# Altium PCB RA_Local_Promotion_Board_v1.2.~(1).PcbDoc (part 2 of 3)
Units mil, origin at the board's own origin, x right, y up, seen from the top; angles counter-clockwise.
Board outline 3390.27 x 5338.61 mil, 4 copper layers (Top Layer, Signal Layer 1, Signal Layer 2, Bottom Layer), stack 30.635 mil thick; 143 components, 181 nets, 726 pads, 394 vias.

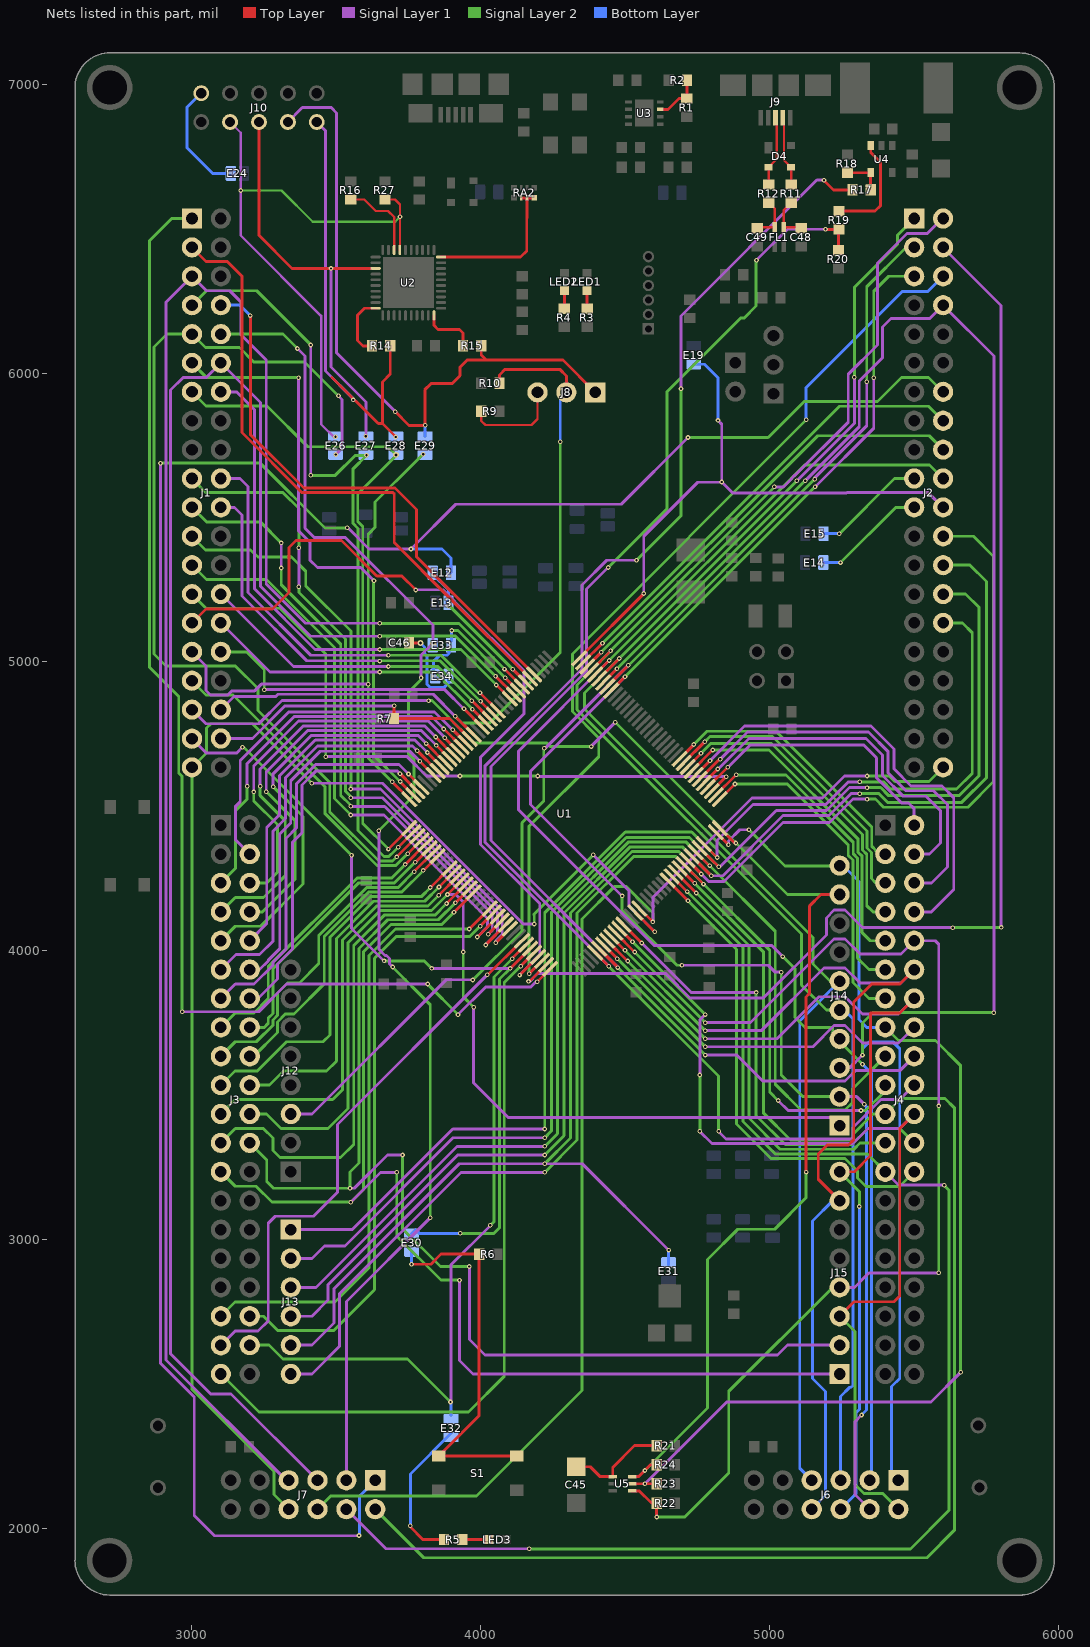
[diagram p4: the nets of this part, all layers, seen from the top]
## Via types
v1: diameter 16, hole 8, Top Layer to Bottom Layer, 368 vias
v2: diameter 19.68, hole 7.87, Top Layer to Bottom Layer, 16 vias
v3: diameter 20, hole 10, Top Layer to Bottom Layer, 7 vias
v4: diameter 16, hole 8, Top Layer to Bottom Layer, tented both sides, 3 vias

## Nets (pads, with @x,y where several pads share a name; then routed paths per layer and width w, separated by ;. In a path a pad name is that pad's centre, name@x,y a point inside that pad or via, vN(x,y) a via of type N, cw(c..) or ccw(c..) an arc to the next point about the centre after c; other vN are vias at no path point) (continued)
NetC45_1: C45.1 R21.2 U5.1 | length 355.9
  Top Layer w10: C45.1@4330,2213.99 4379.01,2213.99 4413.39,2179.61 U5.1@4456.54,2179.61 4456.54,2211.54 4532,2287 R21.2@4608.5,2287
NetC46_1: C46.1 E34.1 | length 325.7
  Top Layer w10: C46.1@3757.5,5066 3790,5066 v3(3791,5066) v3@3794.97,5066
  Bottom Layer w10: v3@3790.02,5065.98 3804.79,5051.21 3804.79,5029.93 3813.65,5021.07 3813.65,4922.93 3824.29,4912.29 3873.53,4912.29 E34.1@3887,4925.76 ; v3@3790.03,5066 v3(3791,5066) ; E34.1@3887,4925.76 3887,4950.36 E34.1@3887.64,4951 3887.64,4926.39 E34.1@3887,4925.76
NetC48_2: C48.2 FL1.2 R11.1 | length 156.8
  Top Layer w8: R11.1@5074,6589.5 5048.87,6564.38 FL1.2@5048.87,6504.54 5105.96,6504.54 C48.2@5109,6501.5
NetC49_2: C49.2 FL1.3 R12.1 | length 155.1
  Top Layer w8: C49.2@4956.61,6501.5 4959.65,6504.54 FL1.3@5017.13,6504.54 5017.13,6569.38 R12.1@4997,6589.5
NetD4_2: D4.2 J9.3 R12.2 | length 246.5
  Top Layer w8: R12.2@4997,6652.5 4997,6711.23 D4.2@4995.63,6712.6 5024,6740.97 J9.3@5024,6886.69
NetD4_3: D4.3 J9.2 R11.2 | length 244.3
  Top Layer w8: J9.2@5049.59,6886.69 5049.59,6736.64 5074,6712.23 R11.2@5074,6652.5
NetE24_2: E24.2 J10.9 | length 397.5
  Bottom Layer w10: J10.9@3032,6969 2983,6920 2983,6780 3072,6691 E24.2@3134.36,6691
NetE26_2: E26.2 J10.8 R27.2 U2.17 | length 2061.7
  Top Layer w8: R27.2@3668,6600.5 3703,6600.5 3720,6583.5 v1(3720,6541) 3720,6426.72 U2.17@3719.47,6426.19
  Signal Layer 1 w8: J10.8@3132,6869 3169,6832 3169,6476 3447,6198 3447,5823 v1@3493.5,5776.5
  Signal Layer 2 w8: v1(3168.87,6632.13) 3309.87,6632.13 3417.87,6524.13 3703.13,6524.13 v1(3720,6541)
  other v1: 3497,5780
NetE27_2: E27.2 J10.6 U2.23 | length 1474.6
  Top Layer w10: J10.6@3232,6869 3232,6477 3346.73,6362.27 v1(3481.27,6362.27) U2.23@3635.81,6362.27
  Signal Layer 1 w10: v1(3481.27,6362.27) 3481.27,6020.73 3602,5900 v1(3602,5781)
NetE28_2: E28.2 J10.2 R14.1 | length 1600.6
  Top Layer w10: 3485,5985 3645,5825 3659.46,5825 ; R14.1@3686.5,6094 3686.5,5996.5 3659.46,5969.46 3659.46,5825 ; v1(3705.76,5778.7) 3659.46,5825
  Signal Layer 1 w10: J10.2@3432,6869 3462,6839 3462,6007 3558,5911 v1(3558,5907)
NetE29_2: E29.2 J8.1 J10.4 R15.1 | length 2353.2
  Top Layer w10: v1(3704,5866) 3751,5819 v1@3806,5819 ; v1(3807,5819) v1@3806,5819 ; R15.1@4001.5,6095 4001.5,6062.5 4019,6045 ; J8.1@4396,5933 4284,6045 4019,6045 ; v1@3806,5819 3806,5942 3828,5964 3901,5964 3928,5991 3928,6020 3953,6045 4019,6045
  Signal Layer 1 w10: J10.4@3332,6869 3382,6919 3482,6919 3500.27,6900.73 3500.27,6354.4 3500,6354.13 3500,6070 v1(3704,5866)
  Bottom Layer w10: E29.2@3807,5780.5 v1(3807,5819)
NetE30_2: E30.2 R6.1 S1.1 S1.4 | length 1317.9
  Top Layer w10: v1(3760,2915) 3827,2915 3862,2950 3993.5,2950 3993.5,2390.4 S1.1@3854.16,2251.05 S1.4@4123.84,2251.05
  Bottom Layer w10: v1(3760,2915) E30.2@3760,2958.5
NetE32_2: E32.2 R5.1 | length 516.3
  Top Layer w10: v1(3756,2010) 3756,2005 3799,1962 R5.1@3872.5,1962
  Bottom Layer w10: v1(3756,2010) 3756,2189 E32.2@3896,2329
NetJ8_3: J8.3 R9.2 | length 334.7
  Top Layer w8: R9.2@4001.5,5868 4001.5,5834.5 4016,5820 4175,5820 4196,5841 J8.3@4196,5933
NetLED1_A: LED1.A R3.2 | length 63
  Top Layer w10: R3.2@4368,6222.97 LED1.A@4368,6285.94
NetLED2_A: LED2.A R4.2 | length 64
  Top Layer w10: R4.2@4289,6222.97 LED2.A@4289,6285.94 LED2.A@4289,6286.94
NetLED3_A: LED3.A R5.2 | length 92
  Top Layer w10: R5.2@3935.5,1962 LED3.A@4027.47,1962
NetR1_1: R1.1 R2.2 U3.3 | length 170.2
  Top Layer w10: U3.3@4621.12,6912.8 4648,6912.8 4685.7,6950.5 R1.1@4713,6950.5 4713.5,6950.99 R2.2@4713.5,7013
NetR14_2: R14.2 U2.30 | length 218.3
  Top Layer w10: R14.2@3623.5,6094 3592,6094 3573,6113 3573,6200 3597.42,6224.42 U2.30@3635.81,6224.42
NetR15_2: R15.2 U2.40 | length 190
  Top Layer w10: U2.40@3837.58,6199.81 3837.58,6165.42 3852,6151 3926,6151 3938.5,6138.5 R15.2@3938.5,6095
NetR16_2: R16.2 U2.18 | length 289
  Top Layer w8: R16.2@3550,6600.5 3596.5,6600.5 3635.87,6561.13 3679,6561.13 3700,6540.13 3700,6426.4 U2.18@3699.79,6426.19
NetR17_2: R17.2 R18.2 U4.4 | length 140.4
  Top Layer w10: R18.2@5269,6693.5 5349.35,6693.5 U4.4@5349.5,6693.65 ; R17.2@5349.5,6634 U4.4@5349.5,6693.65 ; U4.4@5349.6,6693.76 U4.4@5349.5,6693.65
NetR19_1: R19.1 U4.3 | length 375
  Top Layer w8: U4.3@5349.6,6788.24 U4.3@5350.5,6789.15
  Top Layer w10: R19.1@5240,6560.5 5364.5,6560.5 5383,6579 5383,6730 5349.6,6763.4 U4.3@5349.6,6788.24
NetRA2_2: RA2.2 RA2.3 RA2.4 U2.10 | length 534
  Top Layer w10: U2.10@3862.19,6401.58 4137.58,6401.58 4159,6423 4159,6462.57 RA2.3@4159.69,6606.57 ; RA2.2@4140,6606.57 RA2.3@4159.69,6606.57 ; RA2.4@4184.78,6606.57 RA2.3@4159.69,6606.57
P000: J2.30 J13.1 U1.140 | length 4247.4
  Top Layer w10: U1.140@4771.61,4369.21 v1(4817.82,4323)
  Signal Layer 1 w10: J13.1@3342,3035 3555,3035 3903,3383 v1(4221,3383) ; v1(4817.82,4323) 4817.82,4381.82 4942,4506 5194,4506 5273,4585 v1(5312,4585)
  Signal Layer 2 w10: v1(4221,3383) 4221,4132 4500.09,4411.09 4729.74,4411.09 v1(4817.82,4323) ; v1(5312,4585) 5393,4585 5418,4560 5647,4560 5701,4614 5701,5101 5667,5135 J2.30@5600,5135
P001: J2.28 J13.2 U1.139 | length 4442.9
  Top Layer w10: U1.139@4757.69,4355.29 4758.71,4355.29 4798.82,4315.18 ; 4798.82,4315.13 4809.95,4304 ; 4810,4304 v1(4823,4291)
  Signal Layer 1 w10: J13.2@3342,2935 3415,2935 3458.5,2978.5 3529.5,2978.5 3904,3353 v1(4221,3353) ; v1(4823,4291) 4827.87,4291 5022.87,4486 5196.63,4486 5275.63,4565 v1(5337,4565)
  Signal Layer 2 w10: v1(4221,3353) 4244,3376 4244,4132.37 4503.63,4392 4721.95,4392 v1(4823,4291) ; v1(5337,4565) 5384,4565 5412,4537 5655,4537 5725,4607 5725,5188 5678,5235 J2.28@5600,5235
P002: J4.17 J13.3 U1.138 | length 4012
  Top Layer w10: U1.138@4745.63,4341.37 U1.138@4743.77,4341.37 4790.15,4295 v1(4792,4295)
  Signal Layer 1 w10: J13.3@3342,2835 3429,2835 3917,3323 v1(4221,3323)
  Signal Layer 2 w10: v1(4221,3323) 4265,3367 4265,4130.75 4510.25,4376 4711,4376 v1(4792,4295) 5019,4068 5019,3538 5108,3449 5261.05,3449 5288,3475.95 5288,3523 J4.17@5400,3635
P003: J2.26 J13.4 U1.137 | length 4718.6
  Top Layer w10: U1.137@4729.85,4327.45 v1(4797.31,4260)
  Signal Layer 1 w10: J13.4@3342,2735 3415,2735 3471,2791 3471,2844 3920,3293 v1(4221,3293) ; v1(4797.31,4260) 4838,4260 5046,4468 5205,4468 5281,4544 v1(5312,4544)
  Signal Layer 2 w10: v1(4221,3293) 4288,3360 4288,4131.12 4516.88,4360 4697.31,4360 v1(4797.31,4260) ; v1(5312,4544) 5378,4544 5408,4514 5665,4514 5750,4599 5750,5278 5693,5335 J2.26@5600,5335
P004: E31.1 J2.24 J13.5 U1.136 | length 5529.9
  Top Layer w10: U1.136@4715.93,4313.53 4763,4266.47 v1(4763,4266)
  Signal Layer 1 w10: J13.5@3342,2635 3415,2635 3492,2712 3492,2830 3925,3263 v1(4221,3263) 4351,3263 v1(4650,2964) ; v1(4763,4266) 4789,4240 4842,4240 5046,4444 5207,4444 5288,4525 v1(5337,4525)
  Signal Layer 2 w10: v1(4221,3263) 4310,3352 4310,4130.49 4523.51,4344 4685,4344 v1(4763,4266) ; v1(5337,4525) 5366,4525 5394,4497 5686,4497 5775,4586 5775,5365 5705,5435 J2.24@5600,5435
  Bottom Layer w10: E31.1@4650,2912.64 v1(4650,2964)
P005: J4.19 J13.6 U1.135 | length 4164.3
  Top Layer w10: U1.135@4702.02,4299.62 v1(4770.63,4231)
  Signal Layer 1 w10: J13.6@3342,2535 3415,2535 3510,2630 3510,2812 3931,3233 v1(4221,3233) ; v1(5029,3482) 5064,3447 v1(5316,3447)
  Signal Layer 2 w10: v1(4221,3233) 4333,3345 4333,4130.86 4529.14,4327 4674.63,4327 v1(4770.63,4231) 5000,4001.63 5000,3511 v1(5029,3482) ; v1(5316,3447) 5331.87,3447 5400,3515.13 J4.19@5400,3535
P006: J4.21 J7.7 U1.134 | length 5322.2
  Top Layer w10: U1.134@4688.1,4285.7 4739.79,4234 v1(4740,4234)
  Signal Layer 2 w10: J7.7@3634.49,2067 3802.49,1899 5544,1899 5639,1994 5639,3457 5607,3489 5454,3489 J4.21@5400,3435 5358,3435 5288,3365 5288,3355.44 5277.56,3345 5071.37,3345 4979,3437.37 4979,3995 v1(4740,4234)
P007: J4.23 U1.133 | length 1482.8
  Top Layer w10: U1.133@4675.22,4271.78 U1.133@4674.18,4271.78 v1(4746,4200)
  Signal Layer 2 w10: v1(4746,4200) 4928,4018 4928,3421 5036,3313 5290.81,3313 5312.81,3335 J4.23@5400,3335
P008: J4.25 J7.8 U1.132 | length 5069.7
  Top Layer w10: U1.132@4660.26,4257.86 4713.11,4205 v1(4714,4205)
  Signal Layer 1 w10: J7.8@3534.49,2067 3671.49,1930 v1(4168,1930) ; J4.25@5400,3235 5446,3189 v1@5604,3189
  Signal Layer 2 w10: v1@4168,1929 5487,1929 5620,2062 5620,3172 v1(5604,3188) ; v1(4714,4205) 4907,4012 4907,3409 5019,3297 5338,3297 J4.25@5400,3235
P009: J4.26 U1.131 | length 1683.3
  Top Layer w10: U1.131@4646.34,4243.66 U1.131@4646.34,4243.94 v1(4717,4173.27)
  Signal Layer 2 w10: v1(4717,4173.27) 4885.14,4005.14 4885.14,3400 5004.14,3281 5261.05,3281 5304,3238.05 5304,3213 5333,3184 5449,3184 J4.26@5500,3235
P014: J2.40 J7.9 U1.124 | length 4435.7
  Top Layer w10: U1.124@4548.9,4146.5 v1(4595.4,4100)
  Signal Layer 1 w10: v1(4595.4,4100) 4595.4,4185.4 4939,4529 5183,4529 5259,4605 v1(5337,4605)
  Signal Layer 2 w10: J7.9@3434.49,2067 3480.49,2113 3985,2113 4350,2478 4350,4110 4462,4222 4504,4222 4595.4,4130.6 v1(4595.4,4100) ; v1(5337,4605) 5414,4605 5433,4586 5551,4586 J2.40@5600,4635
P015: J1.39 J7.10 U1.123 | length 5064.9
  Top Layer w10: U1.123@4534.98,4132.58 v1(4601.56,4066)
  Signal Layer 1 w10: v1(3415,4580) 3660,4580 4147,4093 v1(4185,4093) ; v1(4389,4332) 4513,4208 4513,4155.53 4601.56,4066.97 v1(4601.56,4066)
  Signal Layer 2 w10: J7.10@3334.49,2067 3284,2117.49 3284,2198 3000,2482 J1.39@3000,4635 3050,4685 3050,4771 3065,4786 3209,4786 v1(3415,4580) ; v1(4185,4093) 4185,4124 4183,4126 v1(4389,4332)
P100: J1.1 U1.108 | length 4332.5
  Top Layer w10: v1@4194.18,3892 U1.108@4239.89,3937.71
  Signal Layer 1 w10: v1(2966,3789) 3230.95,3789 3326.95,3885 v1(3816,3885) ; v1(3921,3779) 4017,3875 4172.87,3875 4190.87,3893 v1(4195,3893)
  Signal Layer 2 w10: v1(2966,3789) 2966,4603.95 2954,4615.95 2954,4880.37 2853,4981.37 2853,6458 2930,6535 J1.1@3000,6535 J1.1@2991,6526 ; v1(3816,3885) 3816,3884 v1(3921,3779)
P101: J2.4 U1.107 | length 4391
  Top Layer w10: v1@4168.34,3894 U1.107@4225.97,3951.63 U1.107@4224.63,3951.63
  Signal Layer 1 w10: v1(4165,3894) 4169.13,3894 4196.13,3921 4640.37,3921 4724.37,3837 4977.87,3837 5196,4055.13 5196,4114.05 5222.95,4141 5261.05,4141 5321.05,4081 v1@5637,4081 ; J2.4@5600,6435 5801,6234 v1(5801,4081)
  Signal Layer 2 w10: v1(5634,4079.5) 5635.5,4081 v1(5801,4081)
P102: J2.6 U1.106 | length 3193.1
  Top Layer w10: v1@4170.5,3924 U1.106@4212.05,3965.55
  Signal Layer 2 w10: v1(4167,3921) 4166,3922 4166,4430 4408,4672 4408,4737.07 4317,4828.07 4317,5028 v1@5126,5837
  Bottom Layer w10: v1(5126,5838) 5126,5949 5460,6283 5548,6283 J2.6@5600,6335
P103: J1.29 U1.105 | length 2865.8
  Top Layer w10: J1.29@3000,5135 3048,5183 3279,5183 3336,5240 3336,5396 3360,5420 3517.87,5420 3639.87,5298 3726,5298 v1(3775,5249) ; v1@4134.66,3916 U1.105@4198.13,3979.47
  Signal Layer 1 w10: v1@3775,5250 3868.87,5250 3952.51,5166.36 4118.02,5000.85 4150,4968.87 4150,4821 3999,4670 3999,4368.37 4204,4163.37 4204,3986.13 4134,3916.13 v1(4134,3916)
P104: J3.39 U1.104 | length 2596.3
  Top Layer w10: v1@4137.82,3947 U1.104@4184.21,3993.39
  Signal Layer 2 w10: J3.39@3100,2535 3232,2403 3957,2403 4081,2527 4081,3890 v1(4138,3947)
P105: E30.1 J1.37 U1.103 | length 2929.9
  Top Layer w10: v1(4101.99,3939) U1.103@4170.29,4007.31
  Signal Layer 1 w10: J1.37@3000,4734.21 3049.21,4685 3155,4685 v1(3175,4705) ; v1(3552.5,4330.5) 3552.5,4077.5 v1(3665,3965) ; v1(3830,3939) v1(4101.99,3939)
  Signal Layer 2 w10: v1(3175,4705) 3178,4705 v1(3552.5,4330.5) ; v1(3665,3965) 3804,3965 v1(3830,3939) ; v1(3929,3022) 4046,3022 4065,3041 4065,3902.01 v1(4101.99,3939)
  Bottom Layer w10: E30.1@3760,3021.5 3773.5,3035 3786.5,3022 v1(3929,3022)
P106: E32.1 J3.38 U1.102 | length 2513.4
  Top Layer w10: v1(4108.15,3973) U1.102@4156.37,4021.23
  Signal Layer 1 w10: v1@3896,2440 3896,2912 v1@4033.5,3049.5
  Signal Layer 2 w10: J3.38@3200,2635 3267,2635 3315,2587 3746,2587 v1(3895,2438) ; v1(4033,3050) 4045,3062 4045,3908.88 4108.15,3972.03 v1(4108.15,3973)
  Bottom Layer w10: E32.1@3896,2391.99 v1@3896,2440
P107: J3.37 U1.101 | length 1957.5
  Top Layer w10: v1@4023.31,3916 U1.101@4142.45,4035.15
  Signal Layer 1 w10: J3.37@3100,2634.21 3149.79,2684 3229,2684 3264,2719 3264,3057 3288,3081 3421,3081 3504,3164 3504,3399 v1(4022,3917)
P108/SWDIO: E28.1 J1.13 U1.73 | length 2362.5
  Top Layer w10: v1(3680,4352.18) U1.73@3752.71,4424.89
  Signal Layer 2 w10: J1.13@3000,5935 3049,5886 3260,5886 3401,5745 3678,5745 v3(3706,5717) 3706,5713.61 3574,5581.61 3574,5486 3591,5469 3591,4441.18 v1(3680,4352.18)
P109: E27.1 J1.7 U1.74 | length 2769.8
  Top Layer w10: v1(3713.66,4358) U1.74@3766.63,4410.97
  Signal Layer 1 w10: v1(3411,5646) v1@3411,6096
  Signal Layer 2 w10: J1.7@3000,6235 3050,6285 3224,6285 3411,6098 v1(3411,6097) ; v1(3411,5646) 3496,5646 3565,5715 v1(3604,5715) 3558,5669 3558,5479.37 3575,5462.37 3575,4417 3665,4327 3682.66,4327 3682.66,4327.97 3699,4344.31 ; 3699.48,4343.83 v1(3713.66,4358)
P110: E26.1 J1.9 U1.75 | length 3373
  Top Layer w10: v1(3708.5,4325) U1.75@3780.55,4397.05
  Signal Layer 1 w10: v1(3498,5718) 3519,5739 3519,5909 v1(3507,5921)
  Signal Layer 2 w10: v1(3507,5921) 3390,6038 3214,6038 3164,6088 3047,6088 J1.9@3000,6135 2914,6135 2869,6090 2869,5027 2910,4986 3150,4986 3228,4908 3228,4832 3477,4583 3477,4481 3647,4311 3694.5,4311 v1(3708.5,4325)
P111: J1.33 U1.76 | length 1149.1
  Top Layer w10: v1@3748,4336.66 U1.76@3794.47,4383.13
  Signal Layer 2 w10: J1.33@3000,4935 3049,4886 3142,4886 3461,4567 3461,4474.37 3640.37,4295 3705.37,4295 3746.19,4335.82 v1(3747.16,4335.82)
P112: J3.15 U1.77 | length 1038.1
  Top Layer w10: v1(3738.18,4299) U1.77@3808.39,4369.21 U1.77@3806.21,4369.21
  Signal Layer 2 w10: J3.15@3100,3735 3150,3785 3215.05,3785 3264,3833.95 3264,3944.68 3570.72,4251.4 3690.58,4251.4 v1(3738.18,4299)
P113: J3.16 U1.78 | length 981.7
  Top Layer w10: v1@3772,4304.99 U1.78@3822.31,4355.29
  Signal Layer 2 w10: J3.16@3200,3735 3250,3735 3264,3749 3264,3767.31 3280,3783.31 3280,3938.05 3577.35,4235.4 3701.47,4235.4 v1(3772.48,4306.41)
P114: J3.17 U1.79 | length 1141.8
  Top Layer w10: v1(3769,4274.15) U1.79@3836.23,4341.37
  Signal Layer 2 w10: J3.17@3100,3635 3150,3685 3222.63,3685 3280,3742.37 3280,3760.68 3296,3776.68 3296,3854.05 3330.95,3889 3372,3889 3439,3956 3439,4053.27 3605.13,4219.4 3714.26,4219.4 v1(3769,4274.15)
P115: J3.18 U1.80 | length 1054.6
  Top Layer w10: v1(3801,4278.31) U1.80@3850.15,4327.45
  Signal Layer 2 w10: J3.18@3200,3635 3214,3635 3296,3717 3296,3754.05 3322.95,3781 3353.05,3781 3458,3885.95 3458,4049.65 3611.76,4203.4 3726.09,4203.4 v1(3801,4278.31)
P200/NMI: J1.38 R7.1 U1.57 | length 983.1
  Top Layer w10: v1@3700,4849 3699.5,4848.5 R7.1@3699.5,4804 3891.4,4804 U1.57@3961.5,4733.9
  Signal Layer 1 w10: J1.38@3100,4735 3209,4735 3322,4848 v1(3700,4848)
P201/MD: J1.36 J8.2 R10.1 U1.56 | length 2673.4
  Top Layer w10: v1(3911,4812.24) U1.56@3975.42,4747.82 ; R10.1@4064.5,5965 4064.5,5993.5 4084,6013 4273,6013 4296,5990 J8.2@4296,5933
  Signal Layer 1 w10: J1.36@3100,4835 3145,4880 3290,4880 3298,4888 3835.24,4888 v1(3911,4812.24)
  Signal Layer 2 w10: v1(3911,4812.24) 3934.24,4789 4031,4789 4275,5033 v1(4275,5762)
  Bottom Layer w10: v1(4275,5762) 4275,5912 J8.2@4296,5933
P202: J1.12 J7.3 U1.46 | length 6103.6
  Top Layer w10: v1(4051,4950.63) U1.46@4114.62,4887.01 U1.46@4112.99,4887.01
  Signal Layer 1 w10: J7.3@3434.49,2167 3135.49,2466 3065,2466 2926,2605 2926,5941 2969,5984 3049,5984 J1.12@3100,6035 3237,5898 3237,5262 3410,5089 v1(3650,5089)
  Signal Layer 2 w10: v1@3650,5090 3911.63,5090 v1(4051,4950.63)
P203: E33.2 J1.10 J7.2 | length 4750.1
  Signal Layer 1 w10: v1(3365,6085) 3391,6059 3391,5463 3423,5431 3530.87,5431 3834,5127.87 v3(3834,5065) 3793,5024 v1(3793,4945) ; J7.2@3534.49,2167 3534.49,2785.49 v1(3825,3076) ; v1@3648,4418 3648,4004.63 3668.63,3984 3672.87,3984 3684,3972.87 3684,3955 v1(3695,3944)
  Signal Layer 2 w10: J1.10@3100,6135 3315,6135 v1(3365,6085) ; v1(3647,4416) 3769,4538 3769,4663 3750,4682 3750,4895.13 3793,4938.13 v1(3793,4945) ; v1@3696,3942 3825,3813 v1(3825,3076)
P203_MCU: E33.1 E34.2 U1.45 | length 508.4
  Top Layer w10: v1(4084,4945.47) U1.45@4128.53,4900.93
  Signal Layer 2 w10: v1(3899,5109) 3920.47,5109 v1(4084,4945.47)
  Bottom Layer w10: E34.2@3835.5,4957.99 3835.5,5000.5 3858,5023 3883,5023 3889.65,5029.65 3889.65,5065.98 3899,5075.34 v1(3899,5109) v1@3898.5,5108.5
P204: J1.5 J7.4 U1.44 | length 6637.1
  Top Layer w10: v1(4082,4975.31) U1.44@4142.45,4914.85
  Signal Layer 1 w10: J7.4@3334.49,2167 3326.13,2167 2910,2583.13 2910,6245 J1.5@3000,6335 3050,6285 3131,6285 3169,6247 3169,6133 3257,6045 3257,5270 3393,5134 v1(3650,5134)
  Signal Layer 2 w10: v1@3650,5133 3924.31,5133 v1(4082,4975.31)
P205: E12.2 J2.14 J7.1 | length 7803.1
  Signal Layer 1 w10: v1(2891,5688) 2891,2572 3008,2455 3008,2045 3078,1975 v1@3575,1975 ; v1@3539,5465 3613,5391 v1(3758,5391) 3913,5546 4486,5546 v1(4717,5777)
  Signal Layer 2 w10: v1(2891,5688) 3236,5688 3460,5464 v1(3537.01,5464) v1@3542,5464 ; v1@4720,5777 4994.63,5777 5119.63,5902 5373,5902 5456,5985 5550,5985 J2.14@5600,5935
  Bottom Layer w10: v1(3578,1976) 3580.49,1978.49 3580.49,2113 J7.1@3634.49,2167 ; v1(3758,5391) 3865,5391 3896.5,5359.5 E12.2@3896.5,5309.02
P205_MCU: E12.1 E13.2 U1.43 | length 515.3
  Top Layer w10: v1(4110.15,4975) U1.43@4156.37,4928.77
  Signal Layer 2 w10: v1(3889,5193) 3892.15,5193 v1(4110.15,4975)
  Bottom Layer w10: E12.1@3833.5,5309.02 3833.5,5303.5 3887.64,5249.36 E13.2@3887.64,5193
P206: J1.3 U1.42 | length 2204.3
  Top Layer w10: J1.3@3000,6435 3049,6386 3122,6386 3173,6335 3173,5794 3381,5586 3696,5586 3700,5582 3700,5412.99 3888.99,5224 U1.42@4170.29,4942.69
P207: J1.8 U1.41 | length 1951.1
  Top Layer w10: v1(3202,6199) 3202,5787.63 3387.63,5602 3702.63,5602 3777,5527.63 3777,5363.82 3902.82,5238 3903.5,5238 4184.21,4957.28 U1.41@4184.21,4956.61
  Bottom Layer w10: J1.8@3100,6235 3166,6235 v1(3202,6199)
P208: J1.32 U1.54 | length 1048.4
  Top Layer w10: v1@3943.92,4835 U1.54@4003.26,4775.66
  Signal Layer 1 w10: v1(3250,4904) 3875,4904 v1(3941.59,4837.41)
  Signal Layer 2 w10: J1.32@3100,5035 3189,5035 3250,4974 v1(3250,4904)
P209: J1.30 U1.53 | length 1060.3
  Top Layer w10: v1(3970.76,4836) U1.53@4017.18,4789.58
  Signal Layer 1 w10: J1.30@3100,5135 3270,4965 v1(3650,4965)
  Signal Layer 2 w10: v1(3650,4965) 3841.76,4965 v1(3970.76,4836)
P210: J1.28 U1.52 | length 1110.1
  Top Layer w10: v1(3969,4866) 3969,4865.6 U1.52@4031.1,4803.5
  Signal Layer 1 w10: J1.28@3100,5235 3351,4984 v1(3680,4984)
  Signal Layer 2 w10: v1(3680,4984) 3851,4984 v1(3969,4866)
P211: J1.22 U1.51 | length 1406.8
  Top Layer w10: v1(3999,4863.44) U1.51@4045.02,4817.42
  Signal Layer 1 w10: J1.22@3100,5535 3147,5535 3173,5509 3173,5228.12 3397.12,5004 v1@3650,5004
  Signal Layer 2 w10: v1@3650,5004 3858.44,5004 v1(3999,4863.44)
  other v1: 3650,5003
P212: E15.1 J2.19 | length 391.1
  Signal Layer 2 w10: v1(5241,5444) 5432,5635 J2.19@5500,5635
  Bottom Layer w10: E15.1@5188,5444 v1(5241,5444)
P213: E14.1 J2.21 | length 392.1
  Signal Layer 2 w10: v1(5245,5344) 5436,5535 J2.21@5500,5535
  Bottom Layer w10: E14.1@5187,5344 v1(5245,5344)
P214: J1.20 U1.50 | length 1506.8
  Top Layer w10: v1(3997,4893) 3997.27,4893 U1.50@4058.94,4831.34
  Signal Layer 1 w10: J1.20@3100,5635 3166,5635 3194,5607 3194,5240 3411,5023 v1(3680,5023)
  Signal Layer 2 w10: v1(3680,5023) 3862.06,5023 3992.06,4893 v1(3997,4893)
P300/SWCLK: E29.1 J1.31 U1.72 | length 2069.8
  Top Layer w10: v1(3692.82,4585) U1.72@3752.71,4525.11
  Signal Layer 1 w10: J1.31@3000,5035 3049,4986 3049,4901 3064,4886 3124,4886 3138,4900 3217,4900 3240,4923 v1(3610,4923)
  Signal Layer 2 w10: v1(3692.82,4585) 3610,4667.82 v1(3610,4923) 3610,5442 3634,5466 3634,5554 3775,5695 ; 3775.5,5694.5 3800,5719 v1(3801,5719)
P301: J1.11 U1.71 | length 2090.7
  Top Layer w10: v1(3721,4586) 3721,4584.66 U1.71@3766.63,4539.03
  Signal Layer 1 w10: v1(3369,5984) 3369,5454 3409,5414 3409,5352 3434,5327 3584,5327 v1(3630,5281) ; v1@3720.26,4586 v1(3721,4586)
  Signal Layer 2 w10: J1.11@3000,6035 3051,5984 v1(3369,5984) ; v1@3630,5282 3629,5281 3629,4677.26 3720.26,4586 v1(3721,4586)
P302: J3.14 U1.70 | length 1280.3
  Top Layer w10: v1(3720.13,4613) 3720.87,4613 3740,4593.87 3740,4593.13 3780.18,4552.95 U1.70@3780.55,4552.95
  Signal Layer 1 w10: J3.14@3200,3835 3229,3835 3296,3902 3296,3954.05 3348,4006.05 3348,4376 3381,4409 3381,4574 3430,4623 3710.13,4623 v1(3720.13,4613)
P303: J3.13 U1.69 | length 1382.4
  Top Layer w10: v1(3749.34,4612) U1.69@3794.47,4566.87
  Signal Layer 1 w10: J3.13@3100,3835 3150,3885 3215.05,3885 3280,3949.95 3280,3960.68 3325,4005.68 3325,4389 3362,4426 3362,4578.37 3428.63,4645 3716.34,4645 v1(3749.34,4612)
P304: J3.12 U1.66 | length 1303.4
  Top Layer w10: v1(3789,4656) 3789,4655.85 U1.66@3836.23,4608.63
  Signal Layer 1 w10: J3.12@3200,3935 3234,3935 3264,3965 3264,3967.31 3304,4007.31 3304,4404 3342,4442 3342,4589 3444,4691 3754,4691 v1(3789,4656)
P305: J3.11 U1.65 | length 1412.3
  Top Layer w10: v1(3780,4692.69) U1.65@3850.15,4622.55
  Signal Layer 1 w10: J3.11@3100,3935 3152,3987 3234,3987 3281,4034 3281,4415 3324,4458 3324,4599 3434,4709 3763.69,4709 v1(3780,4692.69)
P306: J3.10 U1.64 | length 1265.8
  Top Layer w10: v1(3815,4686.47) 3814.53,4686 U1.64@3864.07,4636.47
  Signal Layer 1 w10: J3.10@3200,4035 3259,4094 3259,4427 3303,4471 3303,4606 3427,4730 3771.47,4730 v1(3815,4686.47)
P307: J3.9 U1.63 | length 1481.5
  Top Layer w10: v1(3811,4717.37) U1.63@3877.99,4650.38
  Signal Layer 1 w10: v1(3281,4568) 3281,4613 3414,4746 3782.37,4746 v1(3811,4717.37)
  Signal Layer 2 w10: J3.9@3100,4035 3150,4085 3238,4085 3384,4231 3384,4465 v1(3281,4568)
P308: J3.8 U1.62 | length 1350.5
  Top Layer w10: v1(3846,4711) 3846,4710.21 U1.62@3891.9,4664.3
  Signal Layer 1 w10: v1(3257,4551) 3257,4619 3400,4762 3795,4762 v1(3846,4711)
  Signal Layer 2 w10: J3.8@3200,4135 3244,4135 3356,4247 3356,4452 v1(3257,4551)
P309: J3.7 U1.61 | length 1452.7
  Top Layer w10: v1(3844,4740.05) U1.61@3905.82,4678.22
  Signal Layer 1 w10: v1(3236,4570) 3236,4629 3385,4778 3806.05,4778 v1(3844,4740.05)
  Signal Layer 2 w10: J3.7@3100,4135 3150,4185 3248,4185 3323,4260 3323,4450 3236,4537 v1(3236,4570)
P310: J3.6 U1.60 | length 1326.5
  Top Layer w10: v1(3875,4738) 3875,4736.89 U1.60@3919.74,4692.14
  Signal Layer 1 w10: v1(3214,4550) 3214,4640 3369,4795 3818,4795 v1(3875,4738)
  Signal Layer 2 w10: J3.6@3200,4235 3259,4235 3296,4272 3296,4437 3214,4519 v1(3214,4550)
P311: J3.5 U1.59 | length 1304.4
  Top Layer w10: v1(3871.87,4768) 3933.66,4706.21 U1.59@3933.66,4706.06
  Signal Layer 1 w10: v1(3191,4570) 3191,4648 3354,4811 3828.87,4811 v1(3871.87,4768)
  Signal Layer 2 w10: J3.5@3100,4235 3150,4285 3150,4485 3191,4526 v1(3191,4570)
P312: J3.4 U1.58 | length 1246.3
  Top Layer w10: v1(3902.56,4765) U1.58@3947.58,4719.98
  Signal Layer 1 w10: J3.4@3200,4335 3150,4385 3150,4499 3167,4516 3167,4659 3335,4827 3839.74,4827 3901.74,4765 v1(3902.56,4765)
P313: J1.14 U1.47 | length 1803.7
  Top Layer w10: v1(4053.79,4920) U1.47@4100.7,4873.1
  Signal Layer 1 w10: J1.14@3100,5935 3154,5935 3217,5872 3217,5252 3426,5043 v1(3650,5043)
  Signal Layer 2 w10: v1(3650,5043) 3930.79,5043 v1(4053.79,4920)
P400: J4.13 U1.1 | length 1171.1
  Top Layer w10: U1.1@4827.29,4525.11 v1(4879.59,4577.41)
  Signal Layer 2 w10: v1(4879.59,4577.41) 5060.59,4577.41 5272,4366 5272,4330.05 5288,4314.05 5288,3890.43 5343.43,3835 J4.13@5400,3835
P401: J4.11 U1.2 | length 1121.2
  Top Layer w10: U1.2@4813.37,4539.03 4883.34,4609 v1(4884,4609)
  Signal Layer 2 w10: v1(4884,4609) 5056,4609 5289,4376 5289,4335.68 5304,4320.68 5304,3974.43 5343.43,3935 J4.11@5400,3935
P402: J1.27 U1.3 | length 2391.5
  Top Layer w10: U1.3@4799.45,4552.95 4849,4602.5 v1(4849,4603)
  Signal Layer 1 w10: v1@3464,4672 3745,4672 3812,4605 v1(3928,4605) ; v1@4195,4602 4196,4603 v1(4849,4603)
  Signal Layer 2 w10: J1.27@3000,5235 3049,5186 3305,5186 3463,5028 v1(3463,4672) ; v1@3927,4605 v1(3928,4605) v1(4197,4605)
P403: J4.2 U1.4 | length 964
  Top Layer w10: U1.4@4785.53,4566.87 4853.66,4635 v1(4855,4635)
  Signal Layer 1 w10: v1(4855,4635) 4933,4713 5325,4713 5370,4668 5370,4599 5457,4512 5480,4512 5500,4492 J4.2@5500,4435
P404: J4.4 U1.5 | length 1247.1
  Top Layer w10: U1.5@4771.61,4580.79 v1(4820,4629.18)
  Signal Layer 1 w10: v1(4820,4629.18) 4822.05,4629.18 4927.87,4735 5333,4735 5390,4678 5390,4607 5462,4535 5541,4535 5591,4485 5591,4373 5553,4335 J4.4@5500,4335
P405: J4.6 U1.6 | length 1425
  Top Layer w10: U1.6@4757.69,4594.71 4825.99,4663 v1(4829,4663)
  Signal Layer 1 w10: v1(4829,4663) 4923,4757 5342,4757 5410,4689 5410,4616 5472,4554 5567,4554 5615,4506 5615,4290 5560,4235 J4.6@5500,4235
P406: J4.8 U1.7 | length 1593.4
  Top Layer w10: U1.7@4743.77,4608.63 v1(4793.15,4658)
  Signal Layer 1 w10: v1(4793.15,4658) 4913.15,4778 5351,4778 5430,4699 5430,4630 5489,4571 5596,4571 5637,4530 5637,4212 5560,4135 J4.8@5500,4135
P407/USB_VBUS: E19.1 J2.22 U1.36 | length 2129
  Top Layer w10: U1.36@4340.11,5012.29 v1@4564,5236.18
  Signal Layer 1 w10: v1(4564,5237) 4564,5435 4751,5622 v1@4828,5622 ; v1(4821,5836) 4834,5823 v1(4834,5623) 4872,5585 5265.87,5585 5266.87,5586 5549,5586 J2.22@5600,5535
  Bottom Layer w10: E19.1@4737,6030.5 4774.5,6030.5 4821,5984 v1(4821,5836)
P408: J2.16 U1.35 | length 1633.8
  Top Layer w10: U1.35@4354.03,4998.37 v1(4421,5065)
  Signal Layer 2 w10: v1(4421,5065) 5241,5885 5550,5885 J2.16@5600,5835
P409: J2.18 U1.34 | length 1583
  Top Layer w10: U1.34@4367.95,4984.45 v1@4416.84,5033.34
  Signal Layer 2 w10: v1(4417,5033.18) 4417,5033.87 5166.13,5783 5552,5783 J2.18@5600,5735
P410: J2.2 J6.3 J14.5 U1.33 | length 5483.4
  Top Layer w10: U1.33@4381.87,4970.53 4449,5037.66 v1(4449,5039)
  Signal Layer 1 w10: v1(5016,5606) 5048,5606 5075,5633 5075,5634.87 5086.13,5646 5088,5646 5272,5830 5272,5996 5373,6097 5373,6381 5475,6483 5545.11,6483 5597.11,6535 J2.2@5600,6535
  Signal Layer 2 w10: v1@5018.5,5608.5 v1(5016,5606) v1(4449,5039) 4449,5036.69 4333,4920.69 4333,4834.69 5110,4057.69 5110,3881 5196,3795 J14.5@5218,3795
  Bottom Layer w10: J14.5@5242,3795 5258,3795 5288,3765 5288,2495.44 5281.56,2489 5277,2489 5245.51,2457.51 J6.3@5245.51,2167
P411: J2.20 J6.2 J14.4 U1.32 | length 5296.3
  Top Layer w10: U1.32@4396.61,4956.61 U1.32@4395.79,4956.61 v1(4444,5004.82)
  Signal Layer 1 w10: v1(4444,5004.82) 4130,4690.82 4130,4488.07 4599.07,4019 5006,4019 v1(5045,3980)
  Signal Layer 2 w10: v1(4444,5004.82) 5121.18,5682 5553,5682 J2.20@5600,5635 ; v1(5045,3980) 5087,3938 5087,3770 5122,3735 5218,3735 5218,3710 v1(5321,3607)
  Bottom Layer w10: v1(5321,3607) 5352,3576 5352,2173.49 J6.2@5345.51,2167
P412: J2.1 J6.4 J14.6 U1.31 | length 5385.4
  Top Layer w10: U1.31@4409.71,4942.69 v1(4479,5011.99)
  Signal Layer 1 w10: v1(5094,5627) 5293,5826 v1(5293,5986)
  Signal Layer 2 w10: v1(5094,5627) v1(4479,5011.99) 4359,4891.99 4359,4837.13 5150,4046.13 5150,3954 5209,3895 J14.6@5218,3895 ; v1(5293,5986) 5293,6297 5442,6446 5442,6477 J2.1@5500,6535
  Bottom Layer w10: J6.4@5145.51,2167 5104,2208.51 5104,3757 J14.6@5250,3903
P413: J2.8 J6.1 J14.3 U1.30 | length 6781.2
  Top Layer w10: U1.30@4423.63,4928.77 v1(4471,4976.15)
  Signal Layer 1 w10: v1(5123,5627) 5310,5814 5310,5973 5390,6053 5390,6159 5420,6189 5554,6189 J2.8@5600,6235 5776,6059 v1(5776,3786) ; J14.3@5218,3595 5277,3595 v1(5321,3639)
  Signal Layer 2 w10: v1(4471,4976.15) v1@5121.43,5626.57 ; v1(5321,3639) 5321,3750 5357,3786 v1(5776,3786)
  Bottom Layer w10: v1(5321,3639) 5321,3661 5345,3685 5426,3685 5450,3661 5450,2519.95 5422,2491.95 5422,2190.51 J6.1@5445.51,2167
P414: J2.3 J12.3 U1.29 | length 4115.4
  Top Layer w10: U1.29@4437.55,4914.85 4510,4987.31 v1(4510,4988)
  Signal Layer 1 w10: J12.3@3342,3435 3415,3435 3880,3900 v1@3975,3900 ; v1(4219,4701) 4222.72,4701 v1@4508.72,4987 ; v1(5156,5632) 5156,5637.37 5336,5817.37 v1(5336,5970) v1@5336,5971
  Signal Layer 2 w10: v1(3972,3899) 4142,4069 4142,4443 4217.66,4518.66 v1@4217.66,4699.59 ; v1(4510,4988) 4510.87,4988 v1@5156,5633.13 ; v1(5336,5970) 5336,6299 5472,6435 J2.3@5500,6435
P415: J2.5 J6.8 J14.2 U1.28 | length 5782.9
  Top Layer w10: U1.28@4451.47,4900.93 v1(4499,4948.47)
  Signal Layer 1 w10: v1(4489,4190) 4172,4507 4172,4621.47 v1(4499,4948.47) ; v1@4697,3950 4995,3950 5019,3926 v1(5040,3926) ; v1(5157,5606) 5360,5809 v1(5360,5984.25) ; J14.2@5218,3495 5301,3495 v1(5327,3469) ; v1(5318,2393) 5295,2370 5295,2117.51 J6.8@5345.51,2067
  Signal Layer 2 w10: v1(4489,4190) 4489,4140 4679,3950 v1(4696,3950) ; v1(4499,4948.47) 4499,4948.87 5156.13,5606 v1(5157,5606) ; v1(5040,3926) 5040,3570 5115,3495 J14.2@5242,3495 ; v1(5360,5984.25) 5360,6283 5412,6335 J2.5@5500,6335
  Bottom Layer w10: v1(5318,2393) 5335,2410 5335,3461 v1@5329.13,3466.87
P500: J4.20 R17.1 U1.113 | length 5150.1
  Top Layer w10: U1.113@4395.79,3993.39 4395.79,3993.21 4442,3947 v1(4443,3947) ; v1(5188,6667) 5221,6634 R17.1@5286.5,6634
  Signal Layer 1 w10: v1(4443,3947) 4015,4375 4015,4640.63 4350,4975.63 4350,5265.87 4436.13,5352 v1(4539,5352) ; v1(4693,5945.5) 4693,6198 5163,6668 v1@5187,6668 ; v1(4823,3375) 4849,3349 5281.56,3349 5288,3355.44 5288,3388.05 5384.95,3485 5450,3485 J4.20@5500,3535
  Signal Layer 2 w10: v1(4443,3947) 4443,3946.13 4823,3566.13 v1(4823,3375) ; v1(4539,5352) 4693,5506 v1(4693,5945.5)
P501: J4.18 R19.2 R20.1 U1.114 | length 4738.5
  Top Layer w10: U1.114@4409.71,4006.42 U1.114@4409.71,4007.31 4474,3943.01 v1(4474,3942) ; v1(5193,6498) 5193.5,6497.5 R19.2@5240,6497.5 5238,6495.5 R20.1@5238,6425.5
  Signal Layer 1 w10: v1@4440.5,5327.5 v1@4440,5327 ; v1(4441,5327) v1@4440,5327 ; v1(4474,3942) 4474,3942.87 4035,4381.87 4035,4638 4366,4969 4366,5253 v1@4440,5327 ; v1(4777,3639) 4886,3639 4976,3549 5261.05,3549 5297.05,3585 5450,3585 J4.18@5500,3635 ; v1(4954,6391) 5061,6498 v1@5192,6498
  Signal Layer 2 w10: v1(4441,5327) 4644.5,5530.5 4644.5,5935.37 4899.13,6190 4910.63,6190 4952.5,6231.86 v1@4952.5,6391 ; v1(4474,3942) v1(4777,3639)
P502: J4.16 U1.115 | length 1300.3
  Top Layer w10: U1.115@4423.63,4021.23 v1(4472,3972.85)
  Signal Layer 1 w10: v1(4777,3667.85) 5149.8,3667.85 5222.95,3741 5261.05,3741 5321.05,3681 5446,3681 J4.16@5500,3735
  Signal Layer 2 w10: v1(4472,3972.85) v1(4777,3667.85)
P503: J4.14 J6.9 J15.8 U1.116 | length 3356.5
  Top Layer w10: U1.116@4437.55,4033.58 U1.116@4437.55,4035.15 v1(4508.13,3964.56) v1@4508.13,3963 ; J15.8@5218,3235 5293,3235 5349,3291 5349,3785 5450,3785 J4.14@5500,3835
  Signal Layer 1 w10: v1(4777,3695.69) 5025.69,3695.69 5171,3841 5261.05,3841 5321.05,3781 5446,3781 J4.14@5500,3835
  Signal Layer 2 w10: v1(4508.13,3964.56) v1(4777,3695.69) ; J15.8@5242,3235 5310.13,3166.87 v1(5310.13,3114.87)
  Bottom Layer w10: J6.9@5245.51,2067 5299,2120.49 5299,2400.87 5310.13,2412 v1(5310.13,3114.87)
P504: J4.12 J6.10 J15.7 U1.117 | length 3531.8
  Top Layer w10: U1.117@4451.47,4049.07 v1(4499,4001.53) ; J15.7@5218,3135 5218,3159 5168,3209 5168,3297 5199,3328 5273,3328 5291,3346 5291,3823 5353,3885 5450,3885 J4.12@5500,3935
  Signal Layer 1 w10: v1(4777,3723.53) 4970.53,3723.53 5188,3941 5261.05,3941 5313.05,3889 5454,3889 J4.12@5500,3935
  Signal Layer 2 w10: v1(4499,4001.53) v1(4777,3723.53)
  Bottom Layer w10: J6.10@5145.51,2067 5193,2114.49 5193,2474.44 5148,2519.44 5148,3065 5218,3135 J15.7@5242,3135
P505: J4.10 J15.4 R22.1 U1.118 U5.4 | length 4177.5
  Top Layer w10: U1.118@4467.02,4062.98 U1.118@4465.38,4062.98 v1(4532.37,3996) ; U5.4@4523.46,2130.39 4548.61,2130.39 4591,2088 R22.1@4608.5,2088 4608.5,2037.5 4609,2037.99 v1(4609,2040)
  Signal Layer 1 w10: v1(4777,3751.37) 4933.32,3751.37 5222.95,4041 5261.05,4041 5313.05,3989 5454,3989 J4.10@5500,4035 5573,4035 5585,4023 v1(5585,3463) ; J15.4@5242,2835 5293,2835 5343,2885 v1(5585,2885)
  Signal Layer 2 w10: v1(4532.37,3996) v1(4777,3751.37) ; v1(4609,2040) 4706,2040 4858,2192 4858,2475 J15.4@5218,2835 ; v1(5585,2885) v1(5585,3463)
P506: J4.22 J6.7 J15.3 U1.119 | length 3336.8
  Top Layer w10: U1.119@4479.3,4076.9 v1(4525,4031.21) ; J15.3@5242,2735 5292,2785 5430,2785 5450,2805 5450,3385 J4.22@5500,3435
  Signal Layer 1 w10: v1(4758,3375) 4800,3333 5288.18,3333 5340.18,3385 5450,3385 J4.22@5500,3435 ; v1(4758,3570) 4758,3760.21 v1(4777,3779.21)
  Signal Layer 2 w10: v1(4525,4031.21) v1(4777,3779.21) ; v1(4758,3375) v1(4758,3570) ; J15.3@5242,2711 J15.3@5242,2735 5295,2682 5295,2152.46 5326.46,2121 5391.51,2121 J6.7@5445.51,2067
P508: J4.24 U1.120 | length 1615.8
  Top Layer w10: U1.120@4493.22,4090.82 v1(4557,4027)
  Signal Layer 1 w10: v1(4557,4027) 4728,3856 v1(4953,3856)
  Signal Layer 2 w10: v1(4953,3856) 4953,3430 5054,3329 5284.18,3329 5340.18,3385 5450,3385 J4.24@5500,3335
P511: J1.35 J14.9 R24.1 U1.144 U5.6 | length 5206.8
  Top Layer w10: U5.6@4523.46,2179.61 4545.61,2179.61 4587,2221 R24.1@4608.5,2221 ; U1.144@4827.29,4424.89 4879.18,4373 v1(4883,4373) ; v1(5126,3234) 5126,3840.37 5137,3851.37 5137,4154 5178,4195 J14.9@5242,4195
  Signal Layer 1 w10: J1.35@3000,4835 3049,4786 3231,4786 3312,4867 v1@3817,4867 ; v1(4382,4707) 4382,4708 v1(4465,4791)
  Signal Layer 2 w10: v1(3819,4866) 3830.37,4866 3976.37,4720 4226.87,4720 4239.87,4707 v1(4382,4707) ; v1@4466,4790 v1(4883,4373) 5061,4195 J14.9@5242,4195 ; v1(4568,2200.79) 4784.62,2417.41 4784.62,2931.49 4889.13,3036 5017.05,3036 5126,3144.95 v1(5126,3234) v1@5126,3235
P512: J4.15 J14.10 R23.1 U1.143 U5.5 | length 3888.3
  Top Layer w10: U5.5@4523.46,2155 v1(4568,2155) R23.1@4608.5,2155 ; U1.143@4813.37,4410.97 v1(4857,4367.34)
  Signal Layer 1 w10: v1(4568,2155) 4851,2438 5558,2438 v1(5661,2541) ; v1(4857,4367.34) 4857,4380 4896,4419 v1(4928,4419)
  Signal Layer 2 w10: v1(4928,4419) 5053,4294 J14.10@5218,4294 ; J4.15@5400,3735 5446,3689 5574,3689 5661,3602 v1(5661,2541)
  Bottom Layer w10: J14.10@5242,4295 5254,4295 5309,4240 5309,3762 5336,3735 J4.15@5400,3735
P600: J1.23 U1.98 | length 2150.1
  Top Layer w10: v1(4051.79,4028) U1.98@4100.7,4076.9
  Signal Layer 1 w10: v1(3550,4560) 3652.25,4560 4074,4138.25 4074,4056.39 4051.79,4034.18 v1(4051.79,4028)
  Signal Layer 2 w10: J1.23@3000,5435 3047,5388 3203,5388 3228,5363 3345,5363 3394,5314 3394,5263 3550,5107 v1(3550,4560) ; v1@4051.79,4027.92 v1(4051.79,4028)
P601: J1.19 U1.97 | length 2390.2
  Top Layer w10: v1@4017,4021.05 U1.97@4086.78,4090.82
  Signal Layer 1 w10: v1(3370,5260) v1(3370,5395) ; v1(3550,4530) 3659.63,4530 4058,4131.63 4058,4063.02 4017,4022.02 v1(4017,4020)
  Signal Layer 2 w10: J1.19@3000,5635 3049,5586 3315.37,5586 3370,5531.37 v1(3370,5395) ; v1(3370,5260) 3370,5240 3531,5079 3531,4552.13 3550,4533.13 v1(3550,4530) ; v1(4017,4020) v1@4017,4021.05
P602: J1.21 U1.96 | length 2159.5
  Top Layer w10: v1(4025.11,4057) U1.96@4072.86,4104.74
  Signal Layer 1 w10: v1(3309,5325) v1(3309,5412) ; v1(3550,4500) 3667,4500 4039.5,4127.5 4039.5,4071.39 v1(4025.11,4057)
  Signal Layer 2 w10: J1.21@3000,5535 3050,5485 3236,5485 v1(3309,5412) ; v1(3309,5325) 3309,5267 3515,5061 3515,4538.13 3550,4503.13 v1(3550,4500)
P603: J1.25 U1.95 | length 2015.5
  Top Layer w10: v1(3988,4047.73) U1.95@4058.94,4118.66
  Signal Layer 1 w10: v1(3550,4470) 3665,4470 4023.5,4111.5 4023.5,4083.23 v1(3988,4047.73)
  Signal Layer 2 w10: J1.25@3000,5335 3050,5285 3258,5285 3493,5050 3493,4527 v1(3550,4470)
P604: J3.36 U1.94 | length 2137.2
  Top Layer w10: v1(3997.44,4085) U1.94@4045.02,4132.58
  Signal Layer 2 w10: J3.36@3200,2735 3248,2735 3298,2685 3490,2685 3632,2827 3632,3974 3707,4049 3961.44,4049 v1(3997.44,4085)
P605: J3.35 U1.93 | length 2149.6
  Top Layer w10: v1(3960,4075.4) U1.93@4031.1,4146.5
  Signal Layer 2 w10: J3.35@3100,2735 3149,2784 3495,2784 3613,2902 3613,3984 3704.4,4075.4 v1(3960,4075.4)
P608: J3.19 U1.83 | length 1300.9
  Top Layer w10: v1(3825.21,4219) U1.83@3891.9,4285.7
  Signal Layer 2 w10: J3.19@3100,3535 3149,3584 3225.95,3584 3326.95,3685 3454,3685 3478,3709 3478,4047.02 3618.38,4187.4 3793.61,4187.4 v1(3825.21,4219)
P609: J3.20 U1.84 | length 1260
  Top Layer w10: v1(3855,4220.95) U1.84@3905.82,4271.78
  Signal Layer 2 w10: J3.20@3200,3535 3268,3535 3317,3584 3466,3584 3500,3618 3500,4043 3628.4,4171.4 3805.45,4171.4 v1(3855,4220.95)
P610: J3.21 U1.85 | length 1464
  Top Layer w10: v1(3853.89,4192) U1.85@3919.74,4257.86
  Signal Layer 2 w10: J3.21@3100,3435 3150,3485 3487,3485 3521,3519 3521,4037 3639.4,4155.4 3817.29,4155.4 v1(3853.89,4192)
P611: J3.22 J14.1 U1.86 | length 3482.7
  Top Layer w10: v1(3884.73,4195) U1.86@3933.66,4243.94
  Signal Layer 1 w10: v1(3884.73,4195) 3913,4195 3939,4169 v1(3939,3996) v1@3939,3994 ; v1(3975,3805) 3975,3543 4095,3423 5214,3423 J14.1@5242,3395
  Signal Layer 2 w10: J3.22@3200,3435 3258,3435 3308,3385 3471,3385 3540,3454 3540,4028 3651.4,4139.4 3829.13,4139.4 v1(3884.73,4195) ; v1(3939,3996) 3939,3841 v1(3975,3805)
P612: J3.23 U1.87 | length 1730.2
  Top Layer w10: v1(3881.28,4163.72) U1.87@3947.58,4230.02
  Signal Layer 2 w10: J3.23@3100,3335 3150,3385 3247,3385 3280,3352 3280,3309 3305,3284 3514,3284 3560,3330 3560,4018 3665.4,4123.4 3840.97,4123.4 v1(3881.28,4163.72)
P613: J3.24 J15.2 U1.88 | length 4112.9
  Top Layer w10: v1(3912,4166.6) U1.88@3961.5,4216.1
  Signal Layer 1 w10: v1(3547,3178) 3562,3178 3677,3293 v1(3729,3293) ; v1(3960,2907) v1@3961,2906 ; v1@3961,2910 v1@3961,2906 ; J15.2@5242,2635 5061,2635 5027,2601 4014,2601 3961,2654 v1@3961,2906
  Signal Layer 2 w10: J3.24@3200,3335 3259,3276 3259,3201 3282,3178 v1(3547,3178) 3547,3234 3578,3265 3578,4008 3677.4,4107.4 3852.81,4107.4 v1(3912,4166.6) ; v1(3729,3293) 3729,3038 3860,2907 v1(3960,2907)
P614: J3.25 J15.1 U1.89 | length 4160.6
  Top Layer w10: v1(3907,4133.76) U1.89@3975.42,4202.18
  Signal Layer 1 w10: v1(3550,3130) 3653,3233 v1(3709,3233) ; v1(3926,2860) 3926,2582 3973,2535 J15.1@5242,2535
  Signal Layer 2 w10: J3.25@3100,3235 3150,3185 3222,3185 3277,3130 v1(3550,3130) 3594,3174 3594,3997 3688.4,4091.4 3864.64,4091.4 v1(3907,4133.76) ; v1(3709,3233) 3709,3013 3862,2860 v1(3926,2860)
P700: J4.9 U1.8 | length 1155.5
  Top Layer w10: U1.8@4729.85,4622.55 4729.85,4622.85 4802,4695 v1(4803,4695)
  Signal Layer 2 w10: v1(4803,4695) 4998,4695 5305,4388 5305,4342.31 5320,4327.31 5320,4062.69 5347.69,4035 J4.9@5400,4035
P701: J4.7 U1.9 | length 1096.1
  Top Layer w10: U1.9@4715.93,4636.47 4762,4682.53 v1(4762,4684)
  Signal Layer 2 w10: v1(4762,4684) 4796,4718 5006,4718 5321,4403 5321,4348.94 5336,4333.94 5336,4156.06 5357.06,4135 J4.7@5400,4135
P702: J4.5 U1.10 | length 1034.2
  Top Layer w10: U1.10@4702.02,4650.38 4702.02,4650.89 4775,4723.87 v1(4775,4724)
  Signal Layer 2 w10: v1(4775,4724) 4793,4742 5010,4742 5337,4415 5337,4355.56 5352,4340.56 5352,4250 5367,4235 J4.5@5400,4235
P703: J4.3 U1.11 | length 970
  Top Layer w10: U1.11@4689.3,4664.3 U1.11@4688.1,4664.3 4737,4713.21 v1(4737,4714)
  Signal Layer 2 w10: v1(4737,4714) 4783,4760 5021.63,4760 5353,4428.63 5353,4362.19 5368,4347.19 5368,4344 5377,4335 J4.3@5400,4335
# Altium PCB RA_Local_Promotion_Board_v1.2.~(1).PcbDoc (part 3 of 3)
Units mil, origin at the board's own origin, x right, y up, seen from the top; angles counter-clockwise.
Board outline 3390.27 x 5338.61 mil, 4 copper layers (Top Layer, Signal Layer 1, Signal Layer 2, Bottom Layer), stack 30.635 mil thick; 143 components, 181 nets, 726 pads, 394 vias.

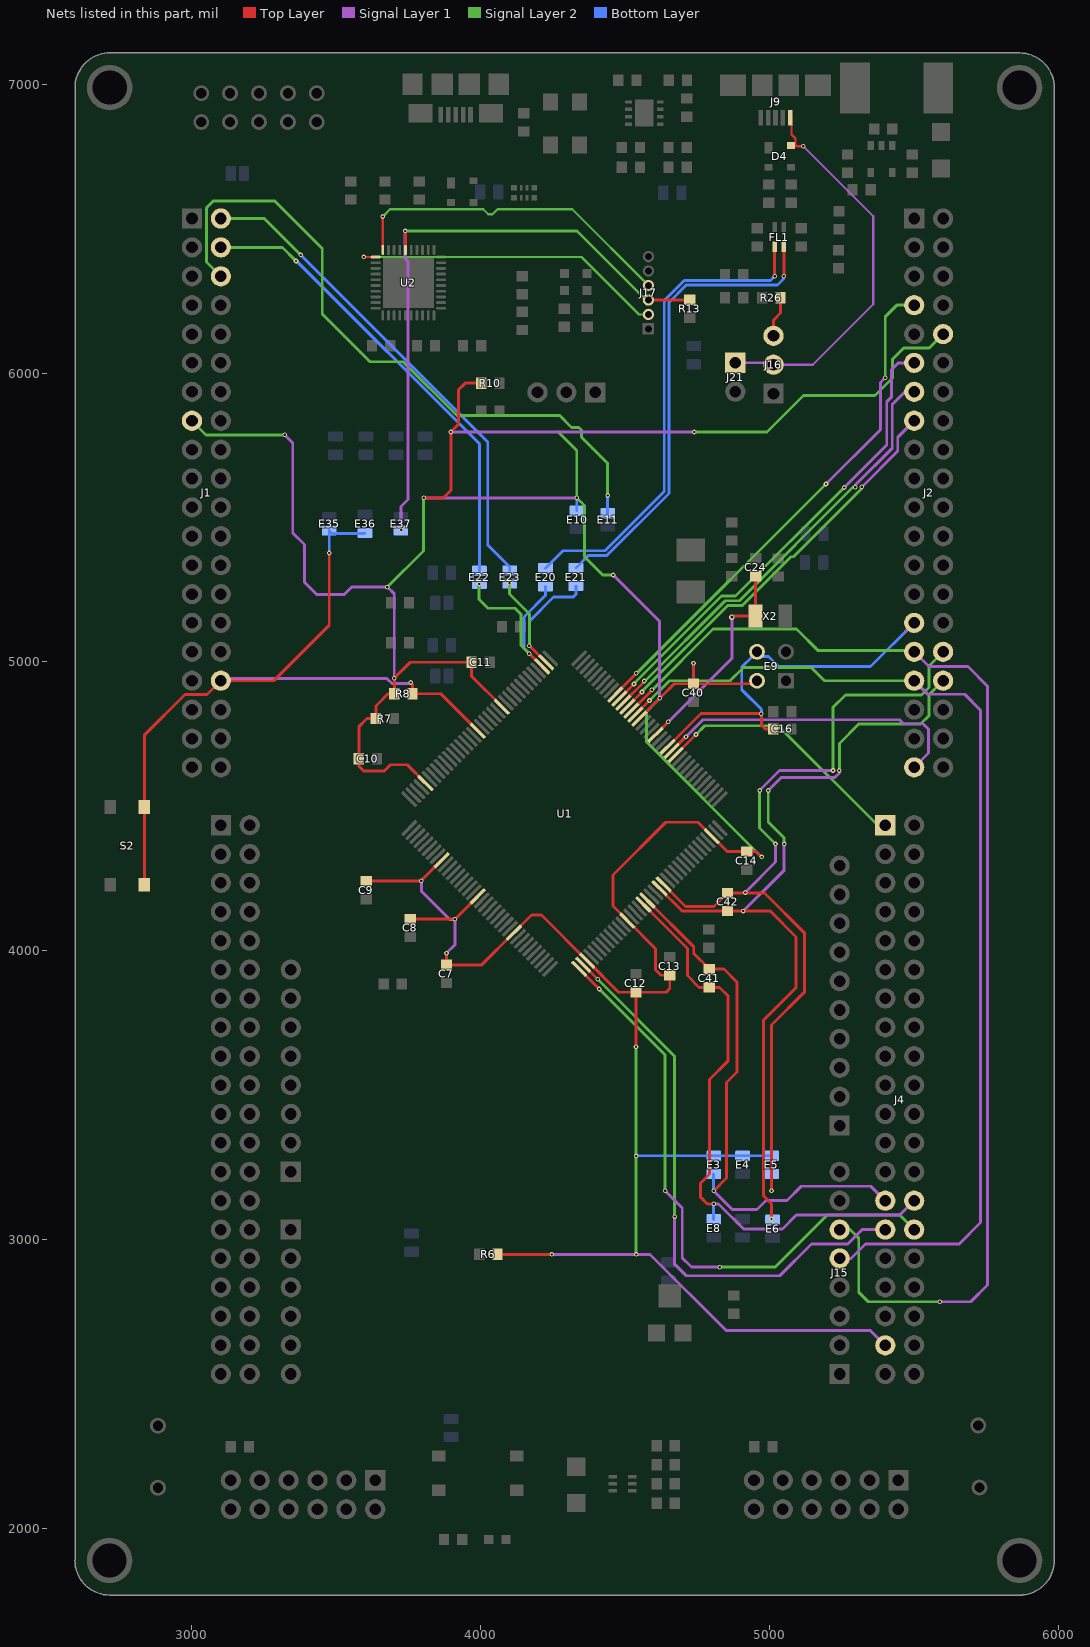
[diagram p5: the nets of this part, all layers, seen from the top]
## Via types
v1: diameter 16, hole 8, Top Layer to Bottom Layer, 368 vias
v2: diameter 19.68, hole 7.87, Top Layer to Bottom Layer, 16 vias
v3: diameter 20, hole 10, Top Layer to Bottom Layer, 7 vias
v4: diameter 16, hole 8, Top Layer to Bottom Layer, tented both sides, 3 vias

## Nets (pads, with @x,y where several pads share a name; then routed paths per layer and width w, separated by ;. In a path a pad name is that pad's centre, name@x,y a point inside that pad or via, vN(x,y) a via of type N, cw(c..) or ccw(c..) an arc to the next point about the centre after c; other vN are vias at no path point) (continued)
P704: J4.1 U1.12 | length 910.1
  Top Layer w10: U1.12@4674.18,4678.22 v1(4744.95,4749)
  Signal Layer 2 w10: v1(4744.95,4749) 4774.95,4779 5029,4779 5373,4435 J4.1@5400,4435
P705: J2.39 U1.13 | length 1100.8
  Top Layer w10: U1.13@4660.26,4692.14 4709.11,4741 v1(4710,4741)
  Signal Layer 1 w10: v1(4710,4741) 4769,4800 5449,4800 5463,4786 5531,4786 5550,4767 5550,4685 J2.39@5500,4635
P708: J2.7 U1.27 | length 1843.7
  Top Layer w10: U1.27@4465.38,4887.01 4538,4959.63 v1(4538,4961)
  Signal Layer 1 w10: v1(5195,5616) 5383,5804 5383,5967.25 v1(5400,5984.25)
  Signal Layer 2 w10: v1(4538,4961) 4539.37,4961 v1@5193,5614.63 ; v1(5400,5984.25) 5400,6195 5440,6235 J2.7@5492,6235 ; J2.7@5500,6235 J2.7@5492,6235 ; J2.7@5515.61,6258.61 J2.7@5492,6235
P709: J2.11 U1.26 | length 1645.5
  Top Layer w10: U1.26@4479.3,4873.1 v1(4530,4923.79)
  Signal Layer 1 w10: v1(5258,5604) 5405,5751 5405,5900.79 5422.11,5917.89 5422.11,6012.11 5445,6035 J2.11@5500,6035
  Signal Layer 2 w10: v1(4530,4923.79) 4530,4924.87 4833.13,5228 4882,5228 v1(5258,5604)
P710: J2.13 U1.25 | length 1538.9
  Top Layer w10: U1.25@4493.22,4859.18 4566,4931.95 v1(4566,4934)
  Signal Layer 1 w10: v1(5296,5605) 5296,5612 5424,5740 5424,5891 5468,5935 J2.13@5500,5935
  Signal Layer 2 w10: v1(4566,4934) 4568.05,4934 4846.05,5212 4895,5212 v1@5288.5,5605.5
P711: J2.15 U1.24 | length 1435.3
  Top Layer w10: U1.24@4507.26,4845.26 U1.24@4507.14,4845.26 v1(4557.89,4896)
  Signal Layer 1 w10: v1(5319,5606) 5443,5730 5443,5778 J2.15@5500,5835
  Signal Layer 2 w10: v1(4557.89,4896) 4557.89,4898.76 4855.13,5196 4906.13,5196 5074.13,5364 5081.87,5364 5317.37,5599.5 v1@5317.37,5606.5
P712: J2.31 J15.6 U1.23 | length 4279.2
  Top Layer w10: U1.23@4521.06,4831.34 4592,4902.27 v1(4592,4904)
  Signal Layer 1 w10: J2.31@5500,5035 5551,4984 5686,4984 5754,4916 5754,2843 5696,2785 v1(5589,2785)
  Signal Layer 2 w10: v1(4592,4904) 4593.73,4904 4803.73,5114 5093,5114 5168,5039 5496,5039 J2.31@5500,5035 ; J15.6@5218,3035 5278,3035 5308,3005 5308,2818 5341,2785 v1(5589,2785)
P713: J2.33 J15.5 U1.22 | length 3637.4
  Top Layer w10: U1.22@4534.98,4817.42 v1(4584,4866.44)
  Signal Layer 1 w10: J15.5@5242,2935 5281,2935 5331,2985 5656,2985 5730,3059 5730,4833 5675,4888 5547,4888 J2.33@5500,4935
  Signal Layer 2 w10: v1(4584,4866.44) 4652.56,4935 4863,4935 4909,4981 5144,4981 5190,4935 J2.33@5500,4935
P800: J4.30 U1.109 | length 2060.1
  Top Layer w10: U1.109@4340.11,3937.71 v1(4410,3867.82)
  Signal Layer 1 w10: v1(4638,3169) 4697,3110 4697,2937 4729,2905 v1(4827,2905)
  Signal Layer 2 w10: v1(4410,3867.82) 4638,3639.82 v1(4638,3169) ; v1(4827,2905) 5019,2905 5199,3085 5450,3085 J4.30@5500,3035
P801: J4.29 U1.110 | length 1980.6
  Top Layer w10: U1.110@4354.03,3951.63 4403.66,3902 v1(4405,3902)
  Signal Layer 1 w10: v1(4671,3080) 4671,2915 4711,2875 5035,2875 5145,2985 5270,2985 5320,3035 J4.29@5400,3035
  Signal Layer 2 w10: v1(4405,3902) 4405,3900.66 4671,3634.66 v1(4671,3080)
RESET#: E35.2 E36.1 J1.34 R8.1 S2.1 S2.4 U1.55 | length 2768.4
  Top Layer w10: S2.1@2833,4498 2834.9,4498 S2.1@2835.05,4497.84 ; S2.4@2835.05,4228.16 S2.1@2835.05,4497.84 ; v1(3475,5377) 3475,5127 3283,4935 J1.34@3100,4935 3052,4887 2976,4887 2835.05,4746.06 S2.1@2835.05,4497.84 ; v1(3757,4929) 3763.5,4922.5 R8.1@3763.5,4890 3861.08,4890 U1.55@3989.34,4761.74
  Signal Layer 1 w10: J1.34@3100,4935 3100,4942 3675.13,4942 3692.13,4925 3753,4925 v1(3757,4929)
  Bottom Layer w10: v1(3475,5377) E35.2@3475,5455.36 3485.36,5445 3597.5,5445 E36.1@3599,5446.5
RESET_OB#: E37.2 J17.3 R13.1 U2.16 | length 2199.7
  Top Layer w10: v1(3738,6492) 3739.16,6490.84 U2.16@3739.16,6426.19 ; J17.3@4580,6253 4722.5,6253 R13.1@4723,6253.5
  Signal Layer 1 w10: v1(3724,5457) 3724,5538 3748.19,5562.19 3748.19,6386.59 3738,6396.78 v1(3738,6492)
  Signal Layer 2 w10: v1(3738,6492) 4333,6492 4572,6253 J17.3@4580,6253
SWCLK_OB: J17.4 U2.20 | length 1169
  Top Layer w8: U2.20@3660.42,6426.19 3660.87,6426.64 v1(3660.87,6542.13)
  Signal Layer 2 w8: v1(3660.87,6542.13) 3685.73,6567 4008.54,6567 4025.54,6550 4040.46,6550 4057.46,6567 4316,6567 J17.4@4580,6303
SWDIO_OB: J17.2 U2.21 | length 1108.2
  Top Layer w8: v1@3595,6401.64 U2.21@3635.81,6401.58
  Signal Layer 2 w8: v1(3595,6402) 4348,6402 4547,6203 J17.2@4580,6203
USB_DM: E21.2 E23.1 U1.38 | length 640.2
  Top Layer w10: v1(4168,5056.34) U1.38@4225.97,4998.37
  Signal Layer 2 w10: v1(4099,5272) 4099,5235 4168,5166 v1(4168,5056.34)
  Bottom Layer w10: v1(4099,5272) 4099.36,5272 E23.1@4100,5271.36 ; v1(4168,5056.34) 4168,5141 4252,5225 4320,5225 4329,5234 E21.2@4329,5262.5
USB_DP: E20.2 E22.1 U1.39 | length 703.4
  Top Layer w10: v1(4168,5028.5) U1.39@4212.05,4984.45
  Signal Layer 2 w10: v1(3994,5270) 3994,5217 4025,5186 4118,5186 4139,5165 4139,5057.5 v1(4168,5028.5)
  Bottom Layer w10: v1(3994,5270) 3994.64,5270 E22.1@3995,5270.36 ; v1(4168,5028.5) 4149,5047.5 4149,5156 4224,5231 E20.2@4224,5261.5
USB_N: E21.1 FL1.1 | length 1628.5
  Top Layer w10: v1@5048.87,6338.13 FL1.1@5048.87,6437.04
  Bottom Layer w10: E21.1@4329,5325.5 4372.5,5369 4436.63,5369 4651,5583.37 4651,6244.37 4711,6304.37 5026.37,6304.37 5048,6326 v1(5048,6335)
USB_P: E20.1 FL1.4 | length 1699.7
  Top Layer w10: v1@5017.13,6336.13 FL1.4@5017.13,6437.04
  Bottom Layer w10: E20.1@4224,5324.5 4284.5,5385 4430,5385 4635,5590 4635,6251 4704.37,6320.37 5002.37,6320.37 v1(5017,6335)
USBFS_VBUS: D4.4 J9.1 J16.2 J21.1 | length 1346.6
  Top Layer w8: J9.1@5075.18,6886.69 5075.18,6826 5088.96,6812.22 5088.96,6787.81 5091.59,6785.18 v1(5116,6785.18)
  Signal Layer 1 w8: J21.1@4881,6036 5006,6036 J16.2@5013,6029 5149,6029 5358,6238 5358,6543.18 v1(5116,6785.18)
USBFS_VBUS_IN: J16.3 R26.2 | length 142.1
  Top Layer w10: J16.3@5013,6129 5013,6183 5037.5,6207.5 R26.2@5037.5,6261
USBPH_N: E23.2 J1.2 | length 1716.2
  Signal Layer 2 w10: J1.2@3100,6535 3250,6535 v1@3375,6410
  Bottom Layer w10: v1@3378,6407 4024,5761 4024,5405 4100,5329 E23.2@4100,5316.64
  other v1: 3376,6409
USBPH_P: E22.2 J1.4 | length 1614
  Signal Layer 2 w10: J1.4@3100,6435 3313,6435 v1@3359,6389
  Bottom Layer w10: v1@3361,6389 3995,5755 E22.2@3995,5315.64
  other v1: 3360,6388
VBAT: C16.1 E9.4 J2.29 U1.14 | length 1380.1
  Top Layer w10: U1.14@4646.34,4706.06 4675.43,4735.15 4676.02,4735.15 4761.87,4821 v1(4971,4821) 4971,4781 4984,4768 C16.1@5012.5,4768
  Signal Layer 1 w10: 5470,5105 J2.29@5500,5135
  Bottom Layer w10: v1(4971,4821) 4971,4836 4903,4904 4903,4982 4940,5019 4996,5019 5031,4984 5349,4984 J2.29@5500,5135
VCC: C7.2 C8.2 C9.2 C10.1 C11.1 C12.1 C13.1 C14.2 C40.1 E3.2 E4.2 E5.2 E9.3 E10.2 J1.15 J2.10 J4.37 R6.2 R7.2 R8.2 R10.2 U1.21 U1.49 U1.68 U1.81 U1.90 U1.99 U1.111 U1.121 U1.142 | length 14242.6
  Top Layer w10: C9.2@3603,4241.5 v1@3792.03,4241.5 ; C8.2@3756,4110.5 3911.58,4110.5 U1.90@3989.34,4188.26 ; v1@3793.27,4242.73 U1.81@3864.07,4313.53 ; v1(3802,5568) 3870,5568 3896,5594 v1(3896,5796) 3923,5823 3923,5942 3946,5965 R10.2@4001.5,5965 ; U1.68@3808.39,4580.79 3745.18,4644 3687,4644 3666,4623 3594,4623 3577.5,4639.5 C10.1@3577.5,4665 3577.5,4775.5 3606,4804 R7.2@3636.5,4804 3636.5,4847.5 3679,4890 R8.2@3700.5,4890 3700.5,4944 3755.5,4999 C11.1@3967.5,4999 3967.5,4950.61 U1.49@4072.86,4845.26 ; v1@3881,3990 C7.2@3881,3951.5 4003.13,3951.5 U1.99@4114.62,4062.98 4175.63,4124 4209.5,4124 U1.111@4367.95,3965.55 4368.32,3965.55 4424,3909.87 4424,3909.5 4476.99,3856.5 C12.1@4537,3856.5 ; R6.2@4056.5,2950 R6.2@4057.5,2949 v1(4245,2949) ; v1(4537,3668) C12.1@4537,3856.5 ; U1.21@4548.9,4803.5 4629,4883.6 ; 4628.78,4883.82 4669.45,4924.5 C40.1@4736,4924.5 ; v1@4736,4993 C40.1@4736,4924.5 ; E9.3@4956,4935 4945.5,4924.5 C40.1@4736,4924.5 ; v1(4972,4325) 4953.5,4343.5 C14.2@4920,4343.5 4853.01,4343.5 U1.142@4799.45,4397.05 4751.5,4445 4640,4445 4457,4262 4457,4154.89 U1.121@4507.14,4104.74 4604,4007.89 4604,3935 4623.5,3915.5 C13.1@4654,3915.5 4654,3869 4641.5,3856.5 C12.1@4537,3856.5
  Signal Layer 1 w10: v1(3321,5786) 3349,5758 3349,5446 3389,5406 3389,5276 3431,5234 3528,5234 3553,5259 v1(3676,5259) ; v1@3677,5259 3700,5236 v1(3700,4944) ; v1(3794,4242) 3794,4206 3891,4109 v1(3910,4109) 3910,4021 v1(3881,3992) ; v1(3802,5568) v4(4332,5568) ; v1(3896,5796) v1(4739,5796) ; v1(4245,2949) v1(4538,2949) 4586,2949 4850,2685 5349.21,2685 J4.37@5400,2634.21 ; v1(4458,5301) 4619,5140 v1(4619,4874)
  Signal Layer 2 w10: J1.15@3000,5835 3049,5786 v1(3321,5786) ; v1(3676,5259) 3801,5384 v1@3801,5567 ; 4267.87,5796 4332,5731.87 v4(4332,5568) 4359,5541 4359,5364 4422,5301 v1(4458,5301) ; v1@4537,2949 v1(4537,3668) ; v1(4619,4874) 4574,4829 4574,4723 v1(4972,4325) ; v1(4739,5796) 4991,5796 5117,5922 5364.62,5922 5425,5982.38 5425,6048 5464,6087 5552,6087 J2.10@5600,6135
  Bottom Layer w10: E10.2@4332,5524.5 v4(4332,5568) ; v1@4540.5,3290.5 E3.2@4806,3290.5 E4.2@4906,3290.5 E5.2@5006,3290.5 ; v1@4733.5,4997.5 v1(4736,4995)
  other v1: 4538,3290
VCC_USB: E11.2 J1.6 | length 2352.1
  Signal Layer 2 w10: J1.6@3100,6335 3050,6385 3050,6572 3073,6595 3287,6595 3451,6431 3451,6204 3616,6039 3731,6039 3917,5853 4273,5853 4314,5812 4338.63,5812 4348,5802.63 4348,5778 4439,5687 v4(4439,5576)
  Bottom Layer w10: E11.2@4439,5514.64 v4(4439,5576)
VREFH: C41.1 E3.1 J4.27 U1.126 | length 1929.9
  Top Layer w10: U1.126@4576.74,4174.34 4737,4014.08 4737,3990.5 C41.1@4791,3936.5 4841.5,3936.5 4887,3891 4887,3581 4850,3544 4850,3213 v1(4806,3169)
  Signal Layer 1 w10: v1(4806,3169) 4870,3105 4955.95,3105 4986.95,3136 5060,3136 5109,3185 5350,3185 J4.27@5400,3135
  Bottom Layer w10: v1(4806,3169) E3.1@4806,3227.5
VREFH0: C42.1 E5.1 J2.32 U1.130 | length 3023.5
  Top Layer w10: U1.130@4632.42,4230.02 4708.93,4153.5 4807.01,4153.5 C42.1@4854,4200.5 4981.5,4200.5 5121,4061 5121,3858 5006,3743 v1(5006,3169)
  Signal Layer 1 w10: v1(4915,4202) 5020,4307 v1(5020,4370) ; v1@4968.13,4555 v1(4965,4555) 5034,4624 v1(5219,4624)
  Signal Layer 2 w10: v1(4965,4555) 4965,4425 v1(5020,4370) ; v1(5219,4624) 5219,4843 5262,4886 5525,4886 5551,4912 5551,4986 J2.32@5600,5035
  Bottom Layer w10: v1(5006,3169) E5.1@5006,3227.5
VREFL: C41.2 E8.2 J4.28 U1.125 | length 2093.6
  Top Layer w10: U1.125@4562.82,4160.42 4715,4008.24 4715,3914 4755.5,3873.5 C41.2@4791,3873.5 4826.5,3873.5 4855,3845 4855,3618 4792,3555 4792,3227 4761,3196 4761,3147 4784,3124 v1(4806,3124)
  Signal Layer 1 w10: v1(4806,3124) 4823,3124 4910,3037 5044,3037 5092,3085 5450,3085 J4.28@5500,3135
  Bottom Layer w10: E8.2@4806,3070.5 v1(4806,3124)
VREFL0: C42.2 E6.2 J2.34 U1.129 | length 2939.4
  Top Layer w10: U1.129@4618.5,4216.1 4697.09,4137.5 C42.2@4854,4137.5 v1(4908.5,4137.5) 5001.5,4137.5 5091,4048 5091,3872 4979,3760 4979,3151 5006,3124 v1(5006,3071.5)
  Signal Layer 1 w10: v1(4908.5,4137.5) 5050,4279 v1(5050,4370) ; v1(4995,4555) 5040,4600 5225,4600 5241,4616 v1(5241,4624)
  Signal Layer 2 w10: v1(4995,4555) 4995,4446 5050,4391 v1(5050,4370) ; v1(5241,4624) 5241,4718 5308,4785 5522,4785 5552,4815 5552,4887 J2.34@5600,4935
XCOUT: C24.2 U1.17 X2.2 | length 729.4
  Top Layer w10: U1.17@4604.58,4747.82 4649.76,4793 v1(4649,4793) ; v3@4870,5159 X2.2@4950.82,5159 4950.82,5295.32 C24.2@4952,5296.5
  Signal Layer 1 w10: v1(4649,4793) 4649.76,4793 4870,5013.24 v3@4870,5147
  other v3: 4868.82,5155.06
pads on no net: J1.16 J1.18 J1.24 J1.26 J1.40 J2.9 J2.17 J2.23 J2.25 J2.27 J2.35 J2.37 J3.1 J3.2 J3.3 J3.26 J3.27 J3.28 J3.29 J3.30 J3.31 J3.32 J3.33 J3.34 J3.40 J4.31 J4.32 J4.33 J4.34 J4.35 J4.38 J4.39 J4.40 J10.7 J11.4 J12.1 J12.8 J17.6 RA2.1 U2.1 U2.3 U2.4 U2.6 U2.7 U2.9 U2.22 U2.24 U2.25 U2.26 U2.29 U2.32 U2.33 U2.34 U2.39 U2.41 U5.3
copper on no net:
  other v1: 4694,3979
  other v2: 3684.04,6248.04 3727.35,6248.04 3770.65,6248.04 3813.96,6248.04 3684.04,6291.35 3727.35,6291.35 3770.65,6291.35 3813.96,6291.35 3684.04,6334.65 3727.35,6334.65 3770.65,6334.65 3813.96,6334.65 3684.04,6377.96 3727.35,6377.96 3770.65,6377.96 3813.96,6377.96

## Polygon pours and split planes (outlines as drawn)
GND on Bottom Layer "Top Layer-L1-2" (solid, pour order 4): 2715.15,7118.46 5864.76,7118.46 5901.2,7118.46 5904.71,7114.95 5911.94,7107.71 5922.17,7107.71 5925.29,7107.71 5969.88,7063.13 5969.88,7054.89 5978.43,7046.33 5978.43,7034.24 5984.26,7028.41 5985.56,7027.11 5985.56,6999.19 5985.56,1893.64 5987.24,1891.96 5984.33,1889.06 5984.33,1873.92 5978.51,1868.09 5978.51,1855.99 5969.96,1847.44 5969.96,1839.2 5945.55,1814.8 5945.55,1810.63 5942.11,1807.19 5933.68,1807.19 5933.68,1806.04 5922.25,1794.62 5912.02,1794.62 5904.78,1787.38 5901.59,1784.19 5846.68,1784.19 2720.52,1784.19 2720.21,1783.87 2691.99,1783.87 2685.68,1790.19 2672.68,1790.19 2664.68,1798.19 2658.68,1798.19 2648.68,1808.19 2642.99,1808.19 2620.03,1831.14 2620.03,1837.38 2610.15,1847.26 2610.15,1857.49 2602.92,1864.73 2602.92,1878.69 2598.51,1883.11 2599.41,1884.01 2599.41,1925.19 2599.41,7012.92 2601.68,7015.19 2601.1,7015.77 2601.1,7028.41 2606.92,7034.24 2606.92,7046.33 2615.48,7054.89 2615.48,7063.13 2656.54,7104.19 2661.68,7104.19 2664.68,7107.19 2670.68,7107.19 2672.89,7107.19 2680.65,7114.95 2700.43,7114.95 2702.68,7117.19 2703.94,7118.46 2724.68,7118.46
GND on Signal Layer 1 "SingalLayer1-L2" (solid, remove dead copper, pour order 6): 5970.96,1906.16 5972.82,1904.3 5972.82,1892.08 5970.61,1889.88 5970.61,1882.89 5964.79,1877.07 5964.79,1864.97 5956.96,1857.13 5956.96,1853.16 5951.3,1847.5 5951.3,1840.12 5945.16,1833.98 5945.16,1832.93 5942.73,1832.93 5927.96,1818.16 5927.96,1816.78 5924.65,1813.47 5918.41,1813.47 5908.53,1803.59 5903.41,1803.59 5899.8,1799.97 5887.7,1799.97 5881.87,1794.15 5880.57,1792.85 5848.96,1792.85 2705.92,1792.85 2703.75,1790.68 2702.48,1791.94 2684.92,1791.94 2680.51,1796.36 2666.54,1796.36 2659.31,1803.59 2649.08,1803.59 2639.2,1813.47 2632.96,1813.47 2613.5,1832.93 2612.45,1832.93 2612.45,1837.1 2601.37,1848.18 2601.37,1856.41 2592.82,1864.97 2589.2,1868.59 2589.2,1873.7 2589.2,1887.67 2584.79,1892.08 2584.79,1900.76 2584.04,1901.5 2585.69,1903.15 2585.69,1917.16 2585.69,7015.85 2584.3,7017.24 2587.38,7020.31 2587.38,7037.39 2593.2,7043.21 2593.2,7055.31 2601.76,7063.87 2601.76,7072.1 2612.83,7083.18 2612.83,7087.35 2617.14,7087.35 2626.96,7097.16 2633.96,7104.16 2635.96,7104.16 2636.94,7104.16 2649.46,7116.69 2659.69,7116.69 2666.93,7123.92 2685.95,7123.92 2690.79,7128.77 2692.13,7127.43 2724.96,7127.43 5861.54,7127.43 5863.18,7129.08 5863.92,7128.33 5872.6,7128.33 5874.81,7126.13 5881.79,7126.13 5887.62,7120.3 5899.72,7120.3 5908.27,7111.75 5916.51,7111.75 5916.51,7110.61 5932.96,7094.16 5933.33,7094.53 5938.94,7094.53 5938.94,7092.44 5951.22,7080.16 5951.22,7077.04 5956.16,7072.1 5956.16,7063.87 5964.71,7055.31 5964.71,7043.21 5970.53,7037.39 5970.53,7013.38 5971.84,7012.07 5971.84,6996.16
GND on Top Layer "Top Layer-GND" (solid, pour order 5): 5992.27,6988.22 5988.85,6991.64 5988.85,7018.45 5988.85,7035.66 5979.41,7045.1 5957.26,7067.26 5957.26,7075.59 5952.04,7075.59 5934.83,7092.81 5922.65,7104.98 5909.3,7104.98 5902.32,7104.98 5900.11,7107.19 5897.91,7109.39 5890.92,7109.39 2709.54,7109.39 2709.11,7109.83 2704.27,7104.98 2685.25,7104.98 2675.02,7104.98 2667.78,7097.75 2662.84,7092.81 2659.72,7092.81 2655.55,7092.81 2644.48,7081.73 2631.15,7068.41 2631.15,7064.24 2620.07,7053.16 2615.14,7048.22 2615.14,7045.1 2615.14,7034.87 2607.9,7027.64 2603.49,7023.23 2603.49,7009.26 2603.49,1883.69 2602.36,1882.56 2607.52,1877.41 2607.52,1854.76 2607.52,1844.53 2614.75,1837.3 2624.63,1827.42 2624.63,1821.18 2624.63,1820.13 2644.09,1800.67 2655.17,1789.59 2659.34,1789.59 2667.57,1789.59 2676.13,1781.04 2681.95,1775.21 2694.05,1775.21 2701.03,1775.21 2703.24,1773.01 2703.59,1772.66 5886.57,1772.66 5909.74,1772.66 5918.11,1781.04 5931.61,1794.53 5942.96,1794.53 5944.01,1794.53 5963.48,1813.99 5979.49,1830.01 5979.49,1837.3 5979.49,1847.53 5986.73,1854.76 5991.14,1859.17 5991.14,1873.14 5991.14,6989.87 5992.18,6990.91 5994.27,6993.01 5994.27,7004.22 5994.27,7013.03 5988.85,7018.45 5988.27,7019.03 5988.27,7034.22 5988.27,7029.27 5986.65,7027.64 5986.65,7032.75 5983.03,7036.37

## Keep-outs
Keep-Out Layer:
  lines w3.94: 2596.73,6985.08 2596.73,1887.04 ccw(c2714.81,1889.76) 2717.53,1771.68 5867.6,1771.68 ccw(c5864.88,1889.76) 5982.96,1892.48 ; 2597.12,6985.47 cw(c2715.2,6988.19) 2712.48,7106.27 5862.08,7106.27 cw(c5864.8,6988.19) 5982.88,6990.91 5982.88,1892.56

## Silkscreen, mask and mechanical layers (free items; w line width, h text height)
Top Overlay:
  drawing of 1603 lines, arcs and shapes, not listed
  text "3V3 LDO" at 4183,7042 h80
  text "9" at 2804,6955 h31.5
  text "2" at 3642,6852 h31.5
  text "10" at 2779.41,6851 h31.5
  text "DEVICE" at 5695,6793 h80
  text "DEVICE" at 5695,6793 h80
  text "USB" at 5694,6733 h80
  text "POWER/DEBUG" at 3711,6724 h68
  text "DEBUG / RFP" at 2835,6686 h80
  text "/POWER" at 5694,6678 h80
  text "USBPH_N" at 3171,6523 h31.5
  text "P410" at 5679.95,6521 h31.5
  text "P100" at 2813,6520 h50
  text "P412" at 5312.25,6519 h31.5
  text "P414" at 5325.75,6423 h31.5
  text "P206" at 2833,6421 h50
  text "P101" at 5679.95,6419 h31.5
  text "USBPH_P" at 3171,6418 h31.5
  text "POWER" at 4390,6377 h31.5 r90
  text "P415" at 5327.25,6323 h31.5
  text "P204" at 2833,6321 h50
  text "VCC_USB" at 3171,6320 h31.5
  text "P102" at 5679.95,6319 h31.5
  text "P109" at 2833,6224 h50
  text "P708" at 5322.3,6223 h31.5
  text "P207" at 3171,6219 h31.5
  text "P413" at 5679.95,6219 h31.5
  text "N.C." at 5353.49,6123 h31.5
  text "P110" at 2833,6119 h50
  text "P203" at 3171,6119 h31.5
  text "VCC" at 5679.95,6117 h31.5
  text "P301" at 2833,6022 h50
  text "P202" at 3171,6022 h31.5
  text "P709" at 5323.8,6022 h31.5
  text "GND" at 5679.95,6019 h31.5
  text "BOOT" at 4583,5983 h80
  text "J10" at 3306,5930 h31.5
  text "P108" at 2833,5923 h50
  text "CONFIG" at 4517,5922 h80
  text "P313" at 3171,5921 h31.5
  text "P710" at 5327.25,5920 h31.5
  text "P205" at 5679.95,5918 h31.5
  text "SWD" at 3503,5851.5 h31.5
  text "JTAG" at 3652,5851.5 h31.5
  text "Serial" at 3791,5850.75 h31.5
  text "VCC" at 2833,5822 h50
  text "N.C." at 3171,5820 h31.5
  text "P711" at 5340.74,5819 h31.5
  text "P408" at 5679.95,5818 h31.5
  text "HOST MODE" at 4906,5791 h40
  text "Pin2" at 3320,5784 h31.5
  text "SWDIO" at 3485,5784.5 h31.5
  text "TMS" at 3662,5784.5 h31.5
  text "NC" at 3813,5784.5 h31.5
  text "NORMAL OPERATION" at 4110,5777 h40
  text "GND" at 2833,5725 h50
  text "N.C." at 5353.49,5723 h31.5
  text "P409" at 5679.95,5720 h31.5
  text "N.C." at 3171,5719 h31.5
  text "Pin4" at 3320,5718.5 h31.5
  text "SWCLK" at 3477,5719 h31.5
  text "TCKS" at 3653,5719 h31.5
  text "MD" at 3813,5719 h31.5
  text "SCI/USB BOOT" at 4108,5685 h40
  text "DEVICE MODE" at 4907,5664 h40
  text "TDO" at 3665,5661 h31.5
  text "TXD9" at 3793,5661 h31.5
  text "Pin6" at 3320,5660.5 h31.5
  text "(SWO)" at 3484,5658 h31.5
  text "P212" at 5327.25,5623 h31.5
  text "P601" at 2833,5622 h50
  text "P214" at 3171,5620 h31.5
  text "P411" at 5679.95,5618 h31.5
  text "Pin8" at 3320,5600.5 h31.5
  text "NC" at 3523,5601 h31.5
  text "TDI" at 3671,5601 h31.5
  text "RXD9" at 3793,5601 h31.5
  text "PROGRAMMER CONTROL" at 4117,5585 h40
  text "USB CONFIG" at 4840,5546 h80
  text "Pin10" at 3320,5539 h31.5
  text "NC" at 3523,5539.5 h31.5
  text "RST" at 3670,5539.5 h31.5
  text "RST" at 3806,5539.5 h31.5
  text "P213" at 5327.25,5523 h31.5
  text "P211" at 3171,5521 h31.5
  text "P602" at 2833,5520 h50
  text "P407" at 5679.95,5519 h31.5
  text "Pin1" at 3320,5480 h31.5
  text "VCC" at 3630,5480.5 h31.5
  text "N.C." at 3171,5428 h31.5
  text "N.C." at 5353.49,5424 h31.5
  text "P600" at 2833,5423 h50
  text "P004" at 5679.95,5421 h31.5
  text "Pin3,5" at 3320,5419 h31.5
  text "GND" at 3633,5419.5 h31.5
  text "P603" at 2833,5322 h50
  text "N.C." at 3171,5322 h31.5
  text "N.C." at 5353.49,5319 h31.5
  text "P003" at 5679.95,5319 h31.5
  text "P402" at 2833,5223 h50
  text "P210" at 3171,5221 h31.5
  text "N.C." at 5353.49,5219 h31.5
  text "P001" at 5679.95,5219 h31.5
  text "VBAT" at 5319,5125 h31.5
  text "P103" at 2833,5122 h50
  text "P209" at 3171,5121 h31.5
  text "P000" at 5679.95,5119 h31.5
  text "P712" at 5327.25,5023 h31.5
  text "P300" at 2833,5022 h50
  text "P208" at 3171,5021 h31.5
  text "VREFH0" at 5679.95,5016 h31.5
  text "MCU" at 5157,4942 h31.5 r90
  text "P111" at 2835,4923 h50
  text "RESET#" at 3171,4922 h31.5
  text "P713" at 5327.25,4922 h31.5
  text "VREFL0" at 5679.95,4919 h31.5
  text "CURRENT" at 5202,4889 h31.5 r90
  text "P511" at 2833,4826 h50
  text "N.C." at 5353.49,4821 h31.5
  text "P201" at 3171,4820 h31.5
  text "AVSS0" at 5679.95,4817 h31.5
  text "P105" at 2833,4724 h50
  text "AVCC0" at 5679.95,4723 h31.5
  text "N.C." at 5353.49,4722 h31.5
  text "P200" at 3172,4721 h31.5
  text "P015" at 2833,4622 h50
  text "P705" at 5322.3,4620 h31.5
  text "N.C." at 3173,4618 h31.5
  text "P014" at 5679.95,4616 h31.5
  text "P403" at 5582,4421 h31.5
  text "N.C." at 2942.08,4419 h50
  text "N.C." at 3273,4418 h31.5
  text "P404" at 5582,4321 h31.5
  text "N.C." at 2942.08,4318 h50
  text "P312" at 3273,4318 h31.5
  text "P512" at 5057,4274 h31.5
  text "P405" at 5582,4223 h31.5
  text "P311" at 2931.39,4220 h50
  text "P310" at 3273,4220 h31.5
  text "P511" at 5070.5,4176 h31.5
  text "RESET" at 2687,4135 h40
  text "P406" at 5582,4121 h31.5
  text "P309" at 2925.15,4120 h50
  text "P308" at 3273,4119 h31.5
  text "3V3" at 5080.09,4075 h31.5
  text "P505" at 5582,4023 h31.5
  text "P306" at 3273,4020 h31.5
  text "P307" at 2925.24,4017 h50
  text "GND" at 5076.79,3976 h31.5
  text "P504" at 5582,3922 h31.5
  text "P305" at 2925,3917 h50
  text "N.C." at 3422,3914 h31.5
  text "P412" at 5057,3872 h31.5
  text "P503" at 5582,3822 h31.5
  text "P303" at 2925.24,3818 h50
  text "GND" at 3422,3816 h31.5
  text "P410" at 5057,3774 h31.5
  text "P502" at 5582,3721 h31.5
  text "P112" at 2925.54,3720 h50
  text "GND" at 3422,3717 h31.5
  text "P411" at 5070.5,3673 h31.5
  text "P501" at 5582,3621 h31.5
  text "P114" at 2925.34,3616 h50
  text "5V" at 3422,3616 h31.5
  text "P413" at 5057,3574 h31.5
  text "P608" at 2925.15,3521 h50
  text "P500" at 5582,3519 h31.5
  text "3V3" at 3422,3516 h31.5
  text "P415" at 5057,3472 h31.5
  text "P506" at 5582,3423 h31.5
  text "P414" at 3422,3418 h31.5
  text "P610" at 2925.34,3417 h50
  text "P611" at 5034.14,3374 h31.5
  text "P612" at 2925.54,3318 h50
  text "P508/P507" at 5582,3318 h31.5
  text "3V3" at 3422,3317 h31.5
  text "RA MCU PROMOTION BOARD" at 3760.29,3296 h59.06
  text "P009" at 5582,3223 h31.5
  text "P614" at 2925.34,3218 h50
  text "N.C." at 3467,3217 h31.5
  text "P503" at 5061,3217 h31.5
  text "YCB21RA144LQFPTGB0631" at 4207.39,3210 h40
  text "VREFL" at 5582,3120 h31.5
  text "P504" at 5059,3118 h31.5
  text "N.C." at 2942.08,3117 h50
  text "N.C." at 2942.08,3021 h50
  text "P800" at 5582,3021 h31.5
  text "P000" at 3422,3017 h31.5
  text "P712" at 5065.95,3016 h31.5
  text "N.C." at 5582,2921 h31.5
  text "N.C." at 2942.08,2920 h50
  text "P001" at 3422,2919 h31.5
  text "P713" at 5065.95,2916 h31.5
  text "N.C." at 5582,2820 h31.5
  text "N.C." at 2942.08,2818 h50
  text "P002" at 3422,2818 h31.5
  text "P505" at 5061,2816 h31.5
  text "GND" at 5582,2721 h31.5
  text "P003" at 3422,2719 h31.5
  text "P506" at 5062.5,2717 h31.5
  text "P605" at 2925,2715 h50
  text "N.C." at 5582,2621 h31.5
  text "P004" at 3422,2619 h31.5
  text "P613" at 5067.6,2619 h31.5
  text "P107" at 2925.24,2618 h50
  text "P104" at 2925.34,2521 h50
  text "P005" at 3422,2521 h31.5
  text "N.C." at 5582,2521 h31.5
  text "P614" at 5066.1,2519 h31.5
  text "USER POT" at 4376,2510 h80
  text "USER INPUT" at 3801,2303 h60
  text "SENSOR" at 4232,2299 h80
  text "PMODB" at 5101,2242 h40
  text "PMODA" at 3288,2238 h40
  text "6" at 3036,2151 h31.5
  text "6" at 4846,2147 h31.5
  text "12" at 3011.41,2054 h31.5
  text "7" at 3714,2054 h31.5
  text "12" at 4821.41,2050 h31.5
  text "7" at 5524,2050 h31.5
  text "LED" at 3801,2035 h60
  text "DIGITAL LIGHT" at 4359,1981 h40
  text "SONSOR" at 4419,1923 h40
Bottom Overlay:
  lines w10: 3389,5261 3390,5261 ; 3391,5262 3392,5263 ; 3414,5405 3414,5610 ; 3417,5401 3779,5401 ; 3417,5612 3781,5612 ; 3427,5669 3865,5669 ; 3430,5674 3430,5884 ; 3431,5885 3869,5885 ; 3497,5348 3498,5348 ; 3499,5349 3500,5350 ; 3597,5384 3591,3991 3818.02,3775.33 ; 3617,3678 4686,3678 ; 3618,3604.78 4687.14,3604.78 ; 3621,3533.78 4685.14,3533.78 ; 3784,5404 3784,5613 ; 3868,5676 3868,5880 ; 3875,3461 3875,3747 ; 4018,3460 4018,3746 ; 4163,3461 4163,3747 ; 4313,3461 4313,3747 ; 4689,3746 4689,3460 3617,3460 3617,3748 4689,3748 ; 5084,2922 5084,3113 ; 5084,2927 4729,2927 4729,3118 5084,3118 ; 3706,4899 3936,4899 3936,5367 3706,5367 3706,4899 ; 3946,5215 3946,5409 4384,5409 4384,5215 3946,5215 ; 4724,3180 5078,3180 5078,3372 4724,3372 4724,3180 ; 4983,5271 5228,5271 5228,5501 4983,5501 4983,5271
  text "JTAG/SWD" at 3860,6796 h31.5
  text "(C) - CLOSE" at 5062,6641 h31.5
  text "(O) - OPEN" at 5063,6568 h31.5
  text "USBPH_N" at 3345.05,6523 h31.5
  text "P410" at 5754.11,6521 h31.5
  text "P100" at 2946,6520 h31.5
  text "P412" at 5451,6519 h31.5
  text "E38(C) 3V3->JLinkOB" at 4737,6485 h31.5
  text "j" at 3892,6476 h354.33
  text "E25(C) J11 USB 5V->U3 LDO 5V" at 4738,6420 h31.5
  text "P206" at 2946,6419 h31.5
  text "P414" at 5451,6419 h31.5
  text "USBPH_P" at 3345.05,6418 h31.5
  text "P101" at 5740.62,6417 h31.5
  text "E24(O) J10 Debug GND Detect<->GND" at 4737,6346 h31.5
  text "P204" at 2946,6321 h31.5
  text "VCC_USB" at 3350,6321 h31.5
  text "P415" at 5451,6320 h31.5
  text "P102" at 5754.11,6318 h31.5
  text "E19(C) J9 USB 5V->P407 (MCU, J2)" at 4735,6271 h31.5
  text "P109" at 2946,6222 h31.5
  text "P207" at 3257.63,6221 h31.5
  text "P708" at 5451,6220 h31.5
  text "P413" at 5754.11,6218 h31.5
  text "E26(C) MCU P110 RXD9/TDI/NC<-Debug J10 Pin8" at 4547,6162 h31.5
  text "P110" at 2946,6121 h31.5
  text "N.C." at 5451,6120 h31.5
  text "P203" at 3257.63,6117 h31.5
  text "VCC" at 5735.82,6117 h31.5
  text "E27(C) MCU P109 TXD9/TDO/SWO->Debug J10 Pin6" at 4547,6100.33 h31.5
  text "E28(C) MCU P108 TMS/SWDIO<->Debug J10 Pin2" at 4547,6038.67 h31.5
  text "P202" at 3257.63,6022 h31.5
  text "P709" at 5451,6019 h31.5
  text "P301" at 2946,6018 h31.5
  text "GND" at 5734.32,6017 h31.5
  text "E29(C) MCU P300 TCK/SWCLK<-Debug J10 Pin4" at 4547,5977 h31.5
  text "SWDIO" at 2946,5921 h31.5
  text "P313" at 3252.68,5920 h31.5
  text "P710" at 5451,5919 h31.5
  text "P205" at 5759.06,5918 h31.5
  text "VCC" at 2946,5820 h31.5
  text "N.C." at 3226.44,5820 h31.5
  text "P711" at 5451,5817 h31.5
  text "P408" at 5759.06,5817 h31.5
  text "GND" at 2946,5721 h31.5
  text "N.C." at 3226.44,5718 h31.5
  text "N.C." at 5451,5718 h31.5
  text "P409" at 5757.56,5718 h31.5
  text "E10(C) 3V3->VCC_USB(MCU)" at 4749,5642.25 h31.5
  text "P411" at 5740.62,5620 h31.5
  text "P212" at 5451,5619 h31.5
  text "P601" at 2946,5618 h31.5
  text "P214" at 3254.18,5617 h31.5
  text "E11(O) VCC_USB(J1)->VCC_USB(MCU)" at 4749,5580.44 h31.5
  text "P211" at 3239.19,5522 h31.5
  text "P602" at 2946,5518 h31.5
  text "P213" at 5451,5518 h31.5
  text "USB_VBUS" at 5874.52,5516 h31.5
  text "N.C." at 3226.44,5421 h31.5
  text "P600" at 2946,5420 h31.5
  text "N.C." at 5451,5419 h31.5
  text "P004" at 5760.56,5419 h31.5
  text "N.C." at 3226.44,5322 h31.5
  text "P603" at 2946,5319 h31.5
  text "N.C." at 5451,5318 h31.5
  text "P003" at 5759.06,5317 h31.5
  text "P210" at 3252.68,5221 h31.5
  text "N.C." at 5451,5220 h31.5
  text "P402" at 2946,5219 h31.5
  text "P001" at 5745.57,5217 h31.5
  text "E14(C) MCU XTAL/P213<->J2" at 5227,5191 h31.5
  text "E15(C) MCU EXTAL/P212<->J2" at 5227,5133.33 h31.5
  text "VBAT" at 5451,5121 h31.5
  text "P209" at 3256.13,5120 h31.5
  text "P103" at 2946,5119 h31.5
  text "P000" at 5759.06,5118 h31.5
  text "SWCLK" at 2946,5019 h31.5
  text "P712" at 5451,5019 h31.5
  text "P208" at 3257.63,5018 h31.5
  text "VREFH0" at 5808.55,5018 h31.5
  text "VBAT" at 4895,5017 h31.5
  text "+3V3" at 5228,5017 h31.5
  text "RESET#" at 3305.32,4921 h31.5
  text "P713" at 5451,4920 h31.5
  text "P111" at 2946,4919 h31.5
  text "+3V3_MCU" at 4895,4919 h31.5
  text "VREFL0" at 5800.3,4919 h31.5
  text "+3V3" at 5228,4915 h31.5
  text "N.C." at 5451,4821 h31.5
  text "MD" at 3206.5,4820 h31.5
  text "P511" at 2946,4819 h31.5
  text "AVSS0" at 5790.4,4819 h31.5
  text "N.C." at 5451,4721 h31.5
  text "NMI" at 3215.2,4720 h31.5
  text "P105" at 2946,4719 h31.5
  text "AVCC0" at 5797,4718 h31.5
  text "E20(C) MCU USB_DP<->J9 MicroUSB" at 4722,4670.67 h31.5
  text "P705" at 5451,4622 h31.5
  text "P015" at 2946,4620 h31.5
  text "P014" at 5755.61,4618 h31.5
  text "N.C." at 3226.44,4617 h31.5
  text "E21(C) MCU USB_DM<->J9 MicroUSB" at 4722,4613 h31.5
  text "E22(O) MCU USB_DP<->J1" at 4722,4555.33 h31.5
  text "E23(O) MCU USB_DM<->J1" at 4722,4497.67 h31.5
  text "P704" at 5392,4473 h31.5
  text "P403" at 5665.74,4421 h31.5
  text "N.C." at 3038,4419 h31.5
  text "N.C." at 3315.07,4417 h31.5
  text "E12(C) MCU P205 as GPIO<->J7, J2" at 4723,4411 h31.5
  text "P703" at 5392,4366 h31.5
  text "E13(O) MCU P205 as TSCAP->C18" at 4723,4353.33 h31.5
  text "P312" at 3341.31,4324 h31.5
  text "P404" at 5667.24,4321 h31.5
  text "N.C." at 3038,4316 h31.5
  text "E33(C) MCU P203 as GPIO<->J7, J1" at 4723,4295.67 h31.5
  text "P512" at 5185,4278 h31.5
  text "P702" at 5392,4271 h31.5
  text "E34(O) MCU P203 as TSCAP->C46" at 4723,4238 h31.5
  text "P310" at 3341.31,4224 h31.5
  text "P405" at 5665.74,4218 h31.5
  text "P311" at 3038,4217 h31.5
  text "P511" at 5185,4178 h31.5
  text "P701" at 5392,4167 h31.5
  text "P308" at 3346.25,4124 h31.5
  text "P309" at 3038,4117 h31.5
  text "P406" at 5664.24,4117 h31.5
  text "3V3" at 5185,4075 h31.5
  text "P700" at 5392,4066 h31.5
  text "P306" at 3344.76,4024 h31.5
  text "P307" at 3038,4019 h31.5
  text "P505" at 5665.74,4017 h31.5
  text "GND" at 5185,3974 h31.5
  text "P401" at 5392,3970 h31.5
  text "P304" at 3314.75,3968 h31.5
  text "P504" at 5667.24,3921 h31.5
  text "P305" at 3038,3918 h31.5
  text "N.C." at 3471.17,3915 h31.5
  text "P412" at 5185,3877 h31.5
  text "P302" at 3313.25,3870 h31.5
  text "P400" at 5392,3869 h31.5
  text "GND" at 3477.62,3820 h31.5
  text "P503" at 5665.74,3820 h31.5
  text "P303" at 3038,3818 h31.5
  text "P410" at 5185,3778 h31.5
  text "P113" at 3303.36,3769 h31.5
  text "P512" at 5392,3768 h31.5
  text "P502" at 5665.74,3722 h31.5
  text "GND" at 3477.62,3720 h31.5
  text "P112" at 3038,3718 h31.5
  text "E35   E36   E37  E26-E29" at 4282,3694 h31.5
  text "P411" at 5185,3677 h31.5
  text "P115" at 3303.36,3668 h31.5
  text "P002" at 5392,3667 h31.5
  text "JLinkOB(Default)" at 4665,3630 h31.5
  text "Open  Close Open    Close" at 4294,3626 h31.5
  text "P501" at 5652.25,3622 h31.5
  text "P114" at 3038,3617 h31.5
  text "5V" at 3449.28,3616 h31.5
  text "P413" at 5185,3579 h31.5
  text "P609" at 3310.11,3569 h31.5
  text "P005" at 5392,3568 h31.5
  text "Open  Close Close    Close" at 4294,3556 h31.5
  text "External debug" at 4665,3553 h31.5
  text "P500" at 5665.74,3520 h31.5
  text "P608" at 3038,3519 h31.5
  text "3V3" at 3474.32,3519 h31.5
  text "Debug out" at 4665,3485 h31.5
  text "Close  Open Open    Open" at 4294,3481 h31.5
  text "P415" at 5185,3479 h31.5
  text "P611" at 3293.16,3469 h31.5
  text "P006" at 5392,3468 h31.5
  text "P506" at 5664.24,3421 h31.5
  text "P414" at 3498.91,3419 h31.5
  text "P610" at 3038,3418 h31.5
  text "P611" at 5185,3381 h31.5
  text "P613" at 3306.66,3367 h31.5
  text "P007" at 5392,3365 h31.5
  text "E3(C) MCU VREFH->MCU VCC 3V3" at 4663,3335 h31.5
  text "3V3" at 3474.32,3320 h31.5
  text "P508/P507" at 5801,3319 h31.5
  text "P612" at 3038,3315 h31.5
  text "E4(C) MCU AVCC0->MCU VCC 3V3" at 4663,3273.6 h31.5
  text "P008" at 5392,3270 h31.5
  text "N.C." at 3282.07,3269 h31.5
  text "P503" at 5204,3266 h31.5
  text "P009" at 5664.24,3222 h31.5
  text "P614" at 3038,3219 h31.5
  text "N.C." at 3471.17,3219 h31.5
  text "E5(C) MCU VREFH0->MCU VCC 3V3" at 4663,3212.2 h31.5
  text "VREFH" at 5396,3168 h31.5
  text "N.C." at 3282.07,3167 h31.5
  text "P504" at 5204,3161 h31.5
  text "VREFL" at 5682.54,3121 h31.5
  text "N.C." at 3038,3120 h31.5
  text "E6(C) MCU VREFL0->GND" at 4662,3113.8 h31.5
  text "P801" at 5392,3069 h31.5
  text "N.C." at 3282.07,3066 h31.5
  text "P712" at 5204,3065 h31.5
  text "E7(C) MCU AVSS0->GND" at 4662,3052.4 h31.5
  text "P800" at 5665.74,3022 h31.5
  text "N.C." at 3038,3019 h31.5
  text "P000" at 3504.36,3018 h31.5
  text "E8(C) MCU VREFL->GND" at 4662,2991 h31.5
  text "N.C." at 5378,2971 h31.5
  text "N.C." at 3282.07,2967 h31.5
  text "P713" at 5204,2966 h31.5
  text "N.C." at 5634.55,2920 h31.5
  text "N.C." at 3038,2919 h31.5
  text "P001" at 3490.86,2918 h31.5
  text "N.C." at 5378,2873 h31.5
  text "N.C." at 3282.07,2867 h31.5
  text "N.C." at 5634.55,2822 h31.5
  text "P505" at 5191,2820 h31.5
  text "P002" at 3504.36,2818 h31.5
  text "N.C." at 3038,2817 h31.5
  text "P604" at 3313.1,2769 h31.5
  text "N.C." at 5378,2769 h31.5
  text "P003" at 3504.36,2719 h31.5
  text "P506" at 5191,2719 h31.5
  text "P605" at 3038,2718 h31.5
  text "GND" at 5641,2718 h31.5
  text "E31(C) MCU P004<-User POT1" at 4571,2683 h31.5
  text "P106" at 3306.81,2668 h31.5
  text "VCC" at 5378,2667 h31.5
  text "E30(C) MCU P105<-User KEY S1" at 4571,2623.5 h31.5
  text "N.C." at 5634.55,2621 h31.5
  text "P613" at 5191,2620 h31.5
  text "P004" at 3505.86,2619 h31.5
  text "P107" at 3038,2617 h31.5
  text "N.C." at 3281,2568 h31.5
  text "N.C." at 5378,2568 h31.5
  text "E32(C) MCU P106<-User LED3" at 4571,2564 h31.5
  text "P614" at 5191,2521 h31.5
  text "P104" at 3038,2520 h31.5
  text "N.C." at 5634.55,2520 h31.5
  text "P005" at 3504.36,2518 h31.5
  text "TP3" at 3027,2338 h40
  text "TP1" at 5676,2336 h40
  text "TP2" at 5677,2122 h40
  text "TP4" at 3027,2118 h40
Bottom Solder:
  lines w15: 4987,4935 5025,4935 ; 4987,5035 5025,5035
Mechanical 1:
  lines w3.94: 2596.7,1889.76 ccw(c2714.81,1889.76) 2714.81,1771.65 5873.65,1771.65 ; 2597.09,1889.38 2597.09,6995.09 ; 2597.09,6988.19 cw(c2715.2,6988.19) 2715.2,7106.3 ; 2708.3,7106.3 5864.8,7106.3 cw(c5864.8,6988.19) 5982.91,6988.19 ; 5864.88,1771.65 ccw(c5864.88,1889.76) 5982.99,1889.76 ; 5983,1881 5983,6988.1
